VERSION 5.8 ;
BUSBITCHARS "[]" ;
DIVIDERCHAR "/" ;
UNITS
    DATABASE MICRONS 2000 ;
END UNITS

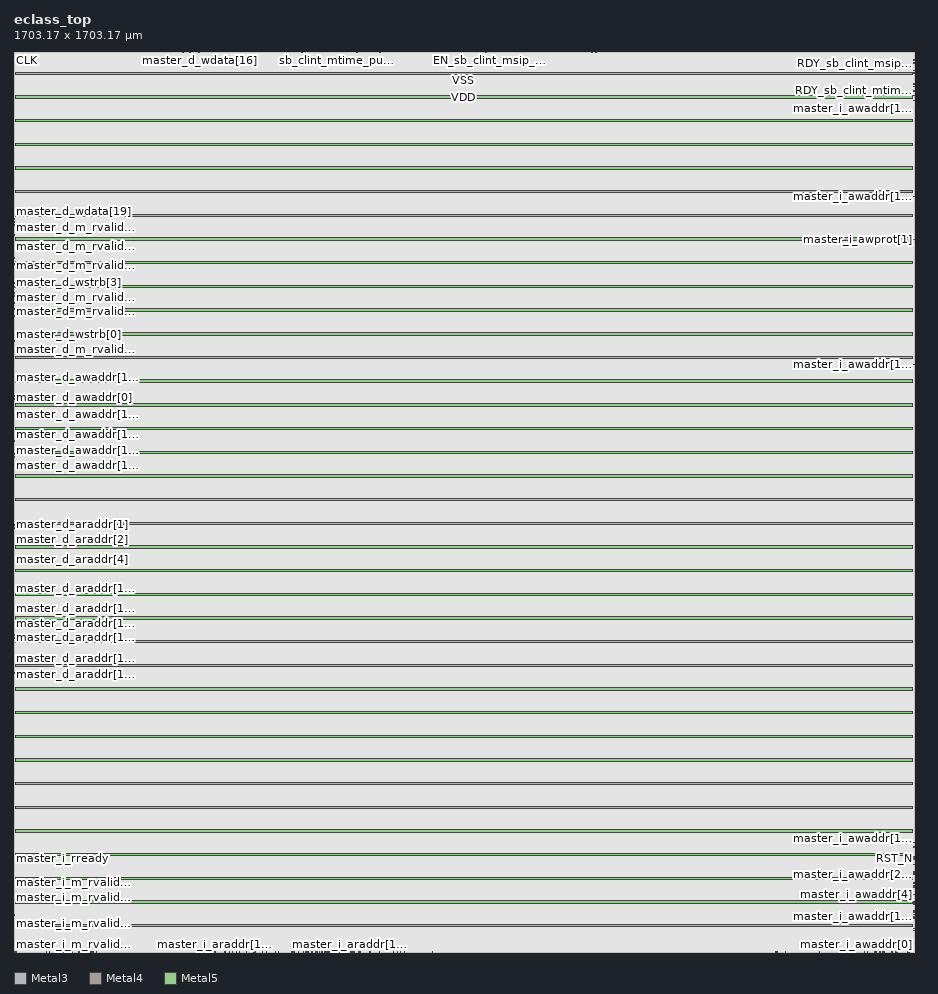
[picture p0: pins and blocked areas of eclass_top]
MACRO eclass_top
  FOREIGN eclass_top 0 0 ;
  CLASS BLOCK ;
  SIZE 1703.175 BY 1703.175 ;
  PIN CLK
    DIRECTION INPUT ;
    USE SIGNAL ;
    PORT
      LAYER Metal3 ;
        RECT  0 1688.26 0.52 1688.54 ;
    END
  END CLK
  PIN EN_sb_clint_msip_put
    DIRECTION INPUT ;
    USE SIGNAL ;
    PORT
      LAYER Metal4 ;
        RECT  900.9 1702.655 901.18 1703.175 ;
    END
  END EN_sb_clint_msip_put
  PIN EN_sb_clint_mtime_put
    DIRECTION INPUT ;
    USE SIGNAL ;
    PORT
      LAYER Metal3 ;
        RECT  0 1243.62 0.52 1243.9 ;
    END
  END EN_sb_clint_mtime_put
  PIN EN_sb_clint_mtip_put
    DIRECTION INPUT ;
    USE SIGNAL ;
    PORT
      LAYER Metal4 ;
        RECT  893.06 1702.655 893.34 1703.175 ;
    END
  END EN_sb_clint_mtip_put
  PIN EN_sb_ext_interrupt_put
    DIRECTION INPUT ;
    USE SIGNAL ;
    PORT
      LAYER Metal4 ;
        RECT  866.18 1702.655 866.46 1703.175 ;
    END
  END EN_sb_ext_interrupt_put
  PIN RDY_sb_clint_msip_put
    DIRECTION OUTPUT ;
    USE SIGNAL ;
    PORT
      LAYER Metal3 ;
        RECT  1702.655 1681.54 1703.175 1681.82 ;
    END
  END RDY_sb_clint_msip_put
  PIN RDY_sb_clint_mtime_put
    DIRECTION OUTPUT ;
    USE SIGNAL ;
    PORT
      LAYER Metal3 ;
        RECT  1702.655 1630.02 1703.175 1630.3 ;
    END
  END RDY_sb_clint_mtime_put
  PIN RDY_sb_clint_mtip_put
    DIRECTION OUTPUT ;
    USE SIGNAL ;
    PORT
      LAYER Metal3 ;
        RECT  1702.655 1662.5 1703.175 1662.78 ;
    END
  END RDY_sb_clint_mtip_put
  PIN RDY_sb_ext_interrupt_put
    DIRECTION OUTPUT ;
    USE SIGNAL ;
    PORT
      LAYER Metal4 ;
        RECT  1643.46 1702.655 1643.74 1703.175 ;
    END
  END RDY_sb_ext_interrupt_put
  PIN RST_N
    DIRECTION INPUT ;
    USE SIGNAL ;
    PORT
      LAYER Metal3 ;
        RECT  1702.655 176.26 1703.175 176.54 ;
    END
  END RST_N
  PIN master_d_araddr[0]
    DIRECTION OUTPUT ;
    USE SIGNAL ;
    PORT
      LAYER Metal3 ;
        RECT  0 782.18 0.52 782.46 ;
    END
  END master_d_araddr[0]
  PIN master_d_araddr[10]
    DIRECTION OUTPUT ;
    USE SIGNAL ;
    PORT
      LAYER Metal3 ;
        RECT  0 686.98 0.52 687.26 ;
    END
  END master_d_araddr[10]
  PIN master_d_araddr[11]
    DIRECTION OUTPUT ;
    USE SIGNAL ;
    PORT
      LAYER Metal3 ;
        RECT  0 689.22 0.52 689.5 ;
    END
  END master_d_araddr[11]
  PIN master_d_araddr[12]
    DIRECTION OUTPUT ;
    USE SIGNAL ;
    PORT
      LAYER Metal3 ;
        RECT  0 665.7 0.52 665.98 ;
    END
  END master_d_araddr[12]
  PIN master_d_araddr[13]
    DIRECTION OUTPUT ;
    USE SIGNAL ;
    PORT
      LAYER Metal3 ;
        RECT  0 660.1 0.52 660.38 ;
    END
  END master_d_araddr[13]
  PIN master_d_araddr[14]
    DIRECTION OUTPUT ;
    USE SIGNAL ;
    PORT
      LAYER Metal3 ;
        RECT  0 636.58 0.52 636.86 ;
    END
  END master_d_araddr[14]
  PIN master_d_araddr[15]
    DIRECTION OUTPUT ;
    USE SIGNAL ;
    PORT
      LAYER Metal3 ;
        RECT  0 524.58 0.52 524.86 ;
    END
  END master_d_araddr[15]
  PIN master_d_araddr[16]
    DIRECTION OUTPUT ;
    USE SIGNAL ;
    PORT
      LAYER Metal3 ;
        RECT  0 527.94 0.52 528.22 ;
    END
  END master_d_araddr[16]
  PIN master_d_araddr[17]
    DIRECTION OUTPUT ;
    USE SIGNAL ;
    PORT
      LAYER Metal3 ;
        RECT  0 523.46 0.52 523.74 ;
    END
  END master_d_araddr[17]
  PIN master_d_araddr[18]
    DIRECTION OUTPUT ;
    USE SIGNAL ;
    PORT
      LAYER Metal3 ;
        RECT  0 609.7 0.52 609.98 ;
    END
  END master_d_araddr[18]
  PIN master_d_araddr[19]
    DIRECTION OUTPUT ;
    USE SIGNAL ;
    PORT
      LAYER Metal3 ;
        RECT  0 570.5 0.52 570.78 ;
    END
  END master_d_araddr[19]
  PIN master_d_araddr[1]
    DIRECTION OUTPUT ;
    USE SIGNAL ;
    PORT
      LAYER Metal3 ;
        RECT  0 807.94 0.52 808.22 ;
    END
  END master_d_araddr[1]
  PIN master_d_araddr[20]
    DIRECTION OUTPUT ;
    USE SIGNAL ;
    PORT
      LAYER Metal3 ;
        RECT  0 546.98 0.52 547.26 ;
    END
  END master_d_araddr[20]
  PIN master_d_araddr[21]
    DIRECTION OUTPUT ;
    USE SIGNAL ;
    PORT
      LAYER Metal3 ;
        RECT  0 620.9 0.52 621.18 ;
    END
  END master_d_araddr[21]
  PIN master_d_araddr[22]
    DIRECTION OUTPUT ;
    USE SIGNAL ;
    PORT
      LAYER Metal3 ;
        RECT  0 594.02 0.52 594.3 ;
    END
  END master_d_araddr[22]
  PIN master_d_araddr[23]
    DIRECTION OUTPUT ;
    USE SIGNAL ;
    PORT
      LAYER Metal3 ;
        RECT  0 608.58 0.52 608.86 ;
    END
  END master_d_araddr[23]
  PIN master_d_araddr[24]
    DIRECTION OUTPUT ;
    USE SIGNAL ;
    PORT
      LAYER Metal3 ;
        RECT  0 633.22 0.52 633.5 ;
    END
  END master_d_araddr[24]
  PIN master_d_araddr[25]
    DIRECTION OUTPUT ;
    USE SIGNAL ;
    PORT
      LAYER Metal3 ;
        RECT  0 622.02 0.52 622.3 ;
    END
  END master_d_araddr[25]
  PIN master_d_araddr[26]
    DIRECTION OUTPUT ;
    USE SIGNAL ;
    PORT
      LAYER Metal3 ;
        RECT  0 599.62 0.52 599.9 ;
    END
  END master_d_araddr[26]
  PIN master_d_araddr[27]
    DIRECTION OUTPUT ;
    USE SIGNAL ;
    PORT
      LAYER Metal3 ;
        RECT  0 567.14 0.52 567.42 ;
    END
  END master_d_araddr[27]
  PIN master_d_araddr[28]
    DIRECTION OUTPUT ;
    USE SIGNAL ;
    PORT
      LAYER Metal3 ;
        RECT  0 568.26 0.52 568.54 ;
    END
  END master_d_araddr[28]
  PIN master_d_araddr[29]
    DIRECTION OUTPUT ;
    USE SIGNAL ;
    PORT
      LAYER Metal3 ;
        RECT  0 670.18 0.52 670.46 ;
    END
  END master_d_araddr[29]
  PIN master_d_araddr[2]
    DIRECTION OUTPUT ;
    USE SIGNAL ;
    PORT
      LAYER Metal3 ;
        RECT  0 781.06 0.52 781.34 ;
    END
  END master_d_araddr[2]
  PIN master_d_araddr[30]
    DIRECTION OUTPUT ;
    USE SIGNAL ;
    PORT
      LAYER Metal3 ;
        RECT  0 669.06 0.52 669.34 ;
    END
  END master_d_araddr[30]
  PIN master_d_araddr[31]
    DIRECTION OUTPUT ;
    USE SIGNAL ;
    PORT
      LAYER Metal3 ;
        RECT  0 645.54 0.52 645.82 ;
    END
  END master_d_araddr[31]
  PIN master_d_araddr[3]
    DIRECTION OUTPUT ;
    USE SIGNAL ;
    PORT
      LAYER Metal3 ;
        RECT  0 757.54 0.52 757.82 ;
    END
  END master_d_araddr[3]
  PIN master_d_araddr[4]
    DIRECTION OUTPUT ;
    USE SIGNAL ;
    PORT
      LAYER Metal3 ;
        RECT  0 741.86 0.52 742.14 ;
    END
  END master_d_araddr[4]
  PIN master_d_araddr[5]
    DIRECTION OUTPUT ;
    USE SIGNAL ;
    PORT
      LAYER Metal3 ;
        RECT  0 738.5 0.52 738.78 ;
    END
  END master_d_araddr[5]
  PIN master_d_araddr[6]
    DIRECTION OUTPUT ;
    USE SIGNAL ;
    PORT
      LAYER Metal3 ;
        RECT  0 711.62 0.52 711.9 ;
    END
  END master_d_araddr[6]
  PIN master_d_araddr[7]
    DIRECTION OUTPUT ;
    USE SIGNAL ;
    PORT
      LAYER Metal3 ;
        RECT  0 740.74 0.52 741.02 ;
    END
  END master_d_araddr[7]
  PIN master_d_araddr[8]
    DIRECTION OUTPUT ;
    USE SIGNAL ;
    PORT
      LAYER Metal3 ;
        RECT  0 712.74 0.52 713.02 ;
    END
  END master_d_araddr[8]
  PIN master_d_araddr[9]
    DIRECTION OUTPUT ;
    USE SIGNAL ;
    PORT
      LAYER Metal3 ;
        RECT  0 721.7 0.52 721.98 ;
    END
  END master_d_araddr[9]
  PIN master_d_arprot[0]
    DIRECTION OUTPUT ;
    USE SIGNAL ;
    PORT
      LAYER Metal3 ;
        RECT  0 663.46 0.52 663.74 ;
    END
  END master_d_arprot[0]
  PIN master_d_arprot[1]
    DIRECTION OUTPUT ;
    USE SIGNAL ;
    PORT
      LAYER Metal3 ;
        RECT  0 564.9 0.52 565.18 ;
    END
  END master_d_arprot[1]
  PIN master_d_arprot[2]
    DIRECTION OUTPUT ;
    USE SIGNAL ;
    PORT
      LAYER Metal3 ;
        RECT  0 566.02 0.52 566.3 ;
    END
  END master_d_arprot[2]
  PIN master_d_arsize[0]
    DIRECTION OUTPUT ;
    USE SIGNAL ;
    PORT
      LAYER Metal3 ;
        RECT  0 804.58 0.52 804.86 ;
    END
  END master_d_arsize[0]
  PIN master_d_arsize[1]
    DIRECTION OUTPUT ;
    USE SIGNAL ;
    PORT
      LAYER Metal3 ;
        RECT  0 802.34 0.52 802.62 ;
    END
  END master_d_arsize[1]
  PIN master_d_arvalid
    DIRECTION OUTPUT ;
    USE SIGNAL ;
    PORT
      LAYER Metal3 ;
        RECT  0 755.3 0.52 755.58 ;
    END
  END master_d_arvalid
  PIN master_d_awaddr[0]
    DIRECTION OUTPUT ;
    USE SIGNAL ;
    PORT
      LAYER Metal3 ;
        RECT  0 1048.74 0.52 1049.02 ;
    END
  END master_d_awaddr[0]
  PIN master_d_awaddr[10]
    DIRECTION OUTPUT ;
    USE SIGNAL ;
    PORT
      LAYER Metal3 ;
        RECT  0 1072.26 0.52 1072.54 ;
    END
  END master_d_awaddr[10]
  PIN master_d_awaddr[11]
    DIRECTION OUTPUT ;
    USE SIGNAL ;
    PORT
      LAYER Metal3 ;
        RECT  0 1065.54 0.52 1065.82 ;
    END
  END master_d_awaddr[11]
  PIN master_d_awaddr[12]
    DIRECTION OUTPUT ;
    USE SIGNAL ;
    PORT
      LAYER Metal3 ;
        RECT  0 1010.66 0.52 1010.94 ;
    END
  END master_d_awaddr[12]
  PIN master_d_awaddr[13]
    DIRECTION OUTPUT ;
    USE SIGNAL ;
    PORT
      LAYER Metal3 ;
        RECT  0 1017.38 0.52 1017.66 ;
    END
  END master_d_awaddr[13]
  PIN master_d_awaddr[14]
    DIRECTION OUTPUT ;
    USE SIGNAL ;
    PORT
      LAYER Metal3 ;
        RECT  0 994.98 0.52 995.26 ;
    END
  END master_d_awaddr[14]
  PIN master_d_awaddr[15]
    DIRECTION OUTPUT ;
    USE SIGNAL ;
    PORT
      LAYER Metal3 ;
        RECT  0 987.14 0.52 987.42 ;
    END
  END master_d_awaddr[15]
  PIN master_d_awaddr[16]
    DIRECTION OUTPUT ;
    USE SIGNAL ;
    PORT
      LAYER Metal3 ;
        RECT  0 963.62 0.52 963.9 ;
    END
  END master_d_awaddr[16]
  PIN master_d_awaddr[17]
    DIRECTION OUTPUT ;
    USE SIGNAL ;
    PORT
      LAYER Metal3 ;
        RECT  0 935.62 0.52 935.9 ;
    END
  END master_d_awaddr[17]
  PIN master_d_awaddr[18]
    DIRECTION OUTPUT ;
    USE SIGNAL ;
    PORT
      LAYER Metal3 ;
        RECT  0 937.86 0.52 938.14 ;
    END
  END master_d_awaddr[18]
  PIN master_d_awaddr[19]
    DIRECTION OUTPUT ;
    USE SIGNAL ;
    PORT
      LAYER Metal3 ;
        RECT  0 959.14 0.52 959.42 ;
    END
  END master_d_awaddr[19]
  PIN master_d_awaddr[1]
    DIRECTION OUTPUT ;
    USE SIGNAL ;
    PORT
      LAYER Metal3 ;
        RECT  0 1000.58 0.52 1000.86 ;
    END
  END master_d_awaddr[1]
  PIN master_d_awaddr[20]
    DIRECTION OUTPUT ;
    USE SIGNAL ;
    PORT
      LAYER Metal3 ;
        RECT  0 962.5 0.52 962.78 ;
    END
  END master_d_awaddr[20]
  PIN master_d_awaddr[21]
    DIRECTION OUTPUT ;
    USE SIGNAL ;
    PORT
      LAYER Metal3 ;
        RECT  0 944.58 0.52 944.86 ;
    END
  END master_d_awaddr[21]
  PIN master_d_awaddr[22]
    DIRECTION OUTPUT ;
    USE SIGNAL ;
    PORT
      LAYER Metal3 ;
        RECT  0 965.86 0.52 966.14 ;
    END
  END master_d_awaddr[22]
  PIN master_d_awaddr[23]
    DIRECTION OUTPUT ;
    USE SIGNAL ;
    PORT
      LAYER Metal3 ;
        RECT  0 943.46 0.52 943.74 ;
    END
  END master_d_awaddr[23]
  PIN master_d_awaddr[24]
    DIRECTION OUTPUT ;
    USE SIGNAL ;
    PORT
      LAYER Metal3 ;
        RECT  0 966.98 0.52 967.26 ;
    END
  END master_d_awaddr[24]
  PIN master_d_awaddr[25]
    DIRECTION OUTPUT ;
    USE SIGNAL ;
    PORT
      LAYER Metal3 ;
        RECT  0 942.34 0.52 942.62 ;
    END
  END master_d_awaddr[25]
  PIN master_d_awaddr[26]
    DIRECTION OUTPUT ;
    USE SIGNAL ;
    PORT
      LAYER Metal3 ;
        RECT  0 941.22 0.52 941.5 ;
    END
  END master_d_awaddr[26]
  PIN master_d_awaddr[27]
    DIRECTION OUTPUT ;
    USE SIGNAL ;
    PORT
      LAYER Metal3 ;
        RECT  0 938.98 0.52 939.26 ;
    END
  END master_d_awaddr[27]
  PIN master_d_awaddr[28]
    DIRECTION OUTPUT ;
    USE SIGNAL ;
    PORT
      LAYER Metal3 ;
        RECT  0 936.74 0.52 937.02 ;
    END
  END master_d_awaddr[28]
  PIN master_d_awaddr[29]
    DIRECTION OUTPUT ;
    USE SIGNAL ;
    PORT
      LAYER Metal3 ;
        RECT  0 969.22 0.52 969.5 ;
    END
  END master_d_awaddr[29]
  PIN master_d_awaddr[2]
    DIRECTION OUTPUT ;
    USE SIGNAL ;
    PORT
      LAYER Metal3 ;
        RECT  0 989.38 0.52 989.66 ;
    END
  END master_d_awaddr[2]
  PIN master_d_awaddr[30]
    DIRECTION OUTPUT ;
    USE SIGNAL ;
    PORT
      LAYER Metal3 ;
        RECT  0 977.06 0.52 977.34 ;
    END
  END master_d_awaddr[30]
  PIN master_d_awaddr[31]
    DIRECTION OUTPUT ;
    USE SIGNAL ;
    PORT
      LAYER Metal3 ;
        RECT  0 1025.22 0.52 1025.5 ;
    END
  END master_d_awaddr[31]
  PIN master_d_awaddr[3]
    DIRECTION OUTPUT ;
    USE SIGNAL ;
    PORT
      LAYER Metal3 ;
        RECT  0 986.02 0.52 986.3 ;
    END
  END master_d_awaddr[3]
  PIN master_d_awaddr[4]
    DIRECTION OUTPUT ;
    USE SIGNAL ;
    PORT
      LAYER Metal3 ;
        RECT  0 1058.82 0.52 1059.1 ;
    END
  END master_d_awaddr[4]
  PIN master_d_awaddr[5]
    DIRECTION OUTPUT ;
    USE SIGNAL ;
    PORT
      LAYER Metal3 ;
        RECT  0 1005.06 0.52 1005.34 ;
    END
  END master_d_awaddr[5]
  PIN master_d_awaddr[6]
    DIRECTION OUTPUT ;
    USE SIGNAL ;
    PORT
      LAYER Metal3 ;
        RECT  0 1066.66 0.52 1066.94 ;
    END
  END master_d_awaddr[6]
  PIN master_d_awaddr[7]
    DIRECTION OUTPUT ;
    USE SIGNAL ;
    PORT
      LAYER Metal3 ;
        RECT  0 1068.9 0.52 1069.18 ;
    END
  END master_d_awaddr[7]
  PIN master_d_awaddr[8]
    DIRECTION OUTPUT ;
    USE SIGNAL ;
    PORT
      LAYER Metal3 ;
        RECT  0 1007.3 0.52 1007.58 ;
    END
  END master_d_awaddr[8]
  PIN master_d_awaddr[9]
    DIRECTION OUTPUT ;
    USE SIGNAL ;
    PORT
      LAYER Metal3 ;
        RECT  0 1071.14 0.52 1071.42 ;
    END
  END master_d_awaddr[9]
  PIN master_d_awprot[0]
    DIRECTION OUTPUT ;
    USE SIGNAL ;
    PORT
      LAYER Metal3 ;
        RECT  0 940.1 0.52 940.38 ;
    END
  END master_d_awprot[0]
  PIN master_d_awprot[1]
    DIRECTION OUTPUT ;
    USE SIGNAL ;
    PORT
      LAYER Metal3 ;
        RECT  0 945.7 0.52 945.98 ;
    END
  END master_d_awprot[1]
  PIN master_d_awprot[2]
    DIRECTION OUTPUT ;
    USE SIGNAL ;
    PORT
      LAYER Metal3 ;
        RECT  0 946.82 0.52 947.1 ;
    END
  END master_d_awprot[2]
  PIN master_d_awsize[0]
    DIRECTION OUTPUT ;
    USE SIGNAL ;
    PORT
      LAYER Metal3 ;
        RECT  0 993.86 0.52 994.14 ;
    END
  END master_d_awsize[0]
  PIN master_d_awsize[1]
    DIRECTION OUTPUT ;
    USE SIGNAL ;
    PORT
      LAYER Metal3 ;
        RECT  0 996.1 0.52 996.38 ;
    END
  END master_d_awsize[1]
  PIN master_d_awvalid
    DIRECTION OUTPUT ;
    USE SIGNAL ;
    PORT
      LAYER Metal3 ;
        RECT  0 1046.5 0.52 1046.78 ;
    END
  END master_d_awvalid
  PIN master_d_bready
    DIRECTION OUTPUT ;
    USE SIGNAL ;
    PORT
      LAYER Metal3 ;
        RECT  0 1052.1 0.52 1052.38 ;
    END
  END master_d_bready
  PIN master_d_m_arready_arready
    DIRECTION INPUT ;
    USE SIGNAL ;
    PORT
      LAYER Metal3 ;
        RECT  0 739.62 0.52 739.9 ;
    END
  END master_d_m_arready_arready
  PIN master_d_m_awready_awready
    DIRECTION INPUT ;
    USE SIGNAL ;
    PORT
      LAYER Metal3 ;
        RECT  0 1049.86 0.52 1050.14 ;
    END
  END master_d_m_awready_awready
  PIN master_d_m_bvalid_bresp[0]
    DIRECTION INPUT ;
    USE SIGNAL ;
    PORT
      LAYER Metal3 ;
        RECT  0 1064.42 0.52 1064.7 ;
    END
  END master_d_m_bvalid_bresp[0]
  PIN master_d_m_bvalid_bresp[1]
    DIRECTION INPUT ;
    USE SIGNAL ;
    PORT
      LAYER Metal3 ;
        RECT  0 1074.5 0.52 1074.78 ;
    END
  END master_d_m_bvalid_bresp[1]
  PIN master_d_m_bvalid_bvalid
    DIRECTION INPUT ;
    USE SIGNAL ;
    PORT
      LAYER Metal3 ;
        RECT  0 1047.62 0.52 1047.9 ;
    END
  END master_d_m_bvalid_bvalid
  PIN master_d_m_rvalid_rdata[0]
    DIRECTION INPUT ;
    USE SIGNAL ;
    PORT
      LAYER Metal3 ;
        RECT  0 1212.26 0.52 1212.54 ;
    END
  END master_d_m_rvalid_rdata[0]
  PIN master_d_m_rvalid_rdata[10]
    DIRECTION INPUT ;
    USE SIGNAL ;
    PORT
      LAYER Metal3 ;
        RECT  0 1239.14 0.52 1239.42 ;
    END
  END master_d_m_rvalid_rdata[10]
  PIN master_d_m_rvalid_rdata[11]
    DIRECTION INPUT ;
    USE SIGNAL ;
    PORT
      LAYER Metal3 ;
        RECT  0 1217.86 0.52 1218.14 ;
    END
  END master_d_m_rvalid_rdata[11]
  PIN master_d_m_rvalid_rdata[12]
    DIRECTION INPUT ;
    USE SIGNAL ;
    PORT
      LAYER Metal3 ;
        RECT  0 1218.98 0.52 1219.26 ;
    END
  END master_d_m_rvalid_rdata[12]
  PIN master_d_m_rvalid_rdata[13]
    DIRECTION INPUT ;
    USE SIGNAL ;
    PORT
      LAYER Metal3 ;
        RECT  0 1335.46 0.52 1335.74 ;
    END
  END master_d_m_rvalid_rdata[13]
  PIN master_d_m_rvalid_rdata[14]
    DIRECTION INPUT ;
    USE SIGNAL ;
    PORT
      LAYER Metal3 ;
        RECT  0 1314.18 0.52 1314.46 ;
    END
  END master_d_m_rvalid_rdata[14]
  PIN master_d_m_rvalid_rdata[15]
    DIRECTION INPUT ;
    USE SIGNAL ;
    PORT
      LAYER Metal3 ;
        RECT  0 1264.9 0.52 1265.18 ;
    END
  END master_d_m_rvalid_rdata[15]
  PIN master_d_m_rvalid_rdata[16]
    DIRECTION INPUT ;
    USE SIGNAL ;
    PORT
      LAYER Metal3 ;
        RECT  0 1262.66 0.52 1262.94 ;
    END
  END master_d_m_rvalid_rdata[16]
  PIN master_d_m_rvalid_rdata[17]
    DIRECTION INPUT ;
    USE SIGNAL ;
    PORT
      LAYER Metal3 ;
        RECT  0 1290.66 0.52 1290.94 ;
    END
  END master_d_m_rvalid_rdata[17]
  PIN master_d_m_rvalid_rdata[18]
    DIRECTION INPUT ;
    USE SIGNAL ;
    PORT
      LAYER Metal3 ;
        RECT  0 1289.54 0.52 1289.82 ;
    END
  END master_d_m_rvalid_rdata[18]
  PIN master_d_m_rvalid_rdata[19]
    DIRECTION INPUT ;
    USE SIGNAL ;
    PORT
      LAYER Metal3 ;
        RECT  0 1313.06 0.52 1313.34 ;
    END
  END master_d_m_rvalid_rdata[19]
  PIN master_d_m_rvalid_rdata[1]
    DIRECTION INPUT ;
    USE SIGNAL ;
    PORT
      LAYER Metal3 ;
        RECT  0 1164.1 0.52 1164.38 ;
    END
  END master_d_m_rvalid_rdata[1]
  PIN master_d_m_rvalid_rdata[20]
    DIRECTION INPUT ;
    USE SIGNAL ;
    PORT
      LAYER Metal3 ;
        RECT  0 1356.74 0.52 1357.02 ;
    END
  END master_d_m_rvalid_rdata[20]
  PIN master_d_m_rvalid_rdata[21]
    DIRECTION INPUT ;
    USE SIGNAL ;
    PORT
      LAYER Metal3 ;
        RECT  0 1336.58 0.52 1336.86 ;
    END
  END master_d_m_rvalid_rdata[21]
  PIN master_d_m_rvalid_rdata[22]
    DIRECTION INPUT ;
    USE SIGNAL ;
    PORT
      LAYER Metal3 ;
        RECT  0 1355.62 0.52 1355.9 ;
    END
  END master_d_m_rvalid_rdata[22]
  PIN master_d_m_rvalid_rdata[23]
    DIRECTION INPUT ;
    USE SIGNAL ;
    PORT
      LAYER Metal3 ;
        RECT  0 1354.5 0.52 1354.78 ;
    END
  END master_d_m_rvalid_rdata[23]
  PIN master_d_m_rvalid_rdata[24]
    DIRECTION INPUT ;
    USE SIGNAL ;
    PORT
      LAYER Metal3 ;
        RECT  0 1353.38 0.52 1353.66 ;
    END
  END master_d_m_rvalid_rdata[24]
  PIN master_d_m_rvalid_rdata[25]
    DIRECTION INPUT ;
    USE SIGNAL ;
    PORT
      LAYER Metal3 ;
        RECT  0 1357.86 0.52 1358.14 ;
    END
  END master_d_m_rvalid_rdata[25]
  PIN master_d_m_rvalid_rdata[26]
    DIRECTION INPUT ;
    USE SIGNAL ;
    PORT
      LAYER Metal3 ;
        RECT  0 1380.26 0.52 1380.54 ;
    END
  END master_d_m_rvalid_rdata[26]
  PIN master_d_m_rvalid_rdata[27]
    DIRECTION INPUT ;
    USE SIGNAL ;
    PORT
      LAYER Metal3 ;
        RECT  0 1376.9 0.52 1377.18 ;
    END
  END master_d_m_rvalid_rdata[27]
  PIN master_d_m_rvalid_rdata[28]
    DIRECTION INPUT ;
    USE SIGNAL ;
    PORT
      LAYER Metal3 ;
        RECT  0 1381.38 0.52 1381.66 ;
    END
  END master_d_m_rvalid_rdata[28]
  PIN master_d_m_rvalid_rdata[29]
    DIRECTION INPUT ;
    USE SIGNAL ;
    PORT
      LAYER Metal3 ;
        RECT  0 1311.94 0.52 1312.22 ;
    END
  END master_d_m_rvalid_rdata[29]
  PIN master_d_m_rvalid_rdata[2]
    DIRECTION INPUT ;
    USE SIGNAL ;
    PORT
      LAYER Metal3 ;
        RECT  0 1187.62 0.52 1187.9 ;
    END
  END master_d_m_rvalid_rdata[2]
  PIN master_d_m_rvalid_rdata[30]
    DIRECTION INPUT ;
    USE SIGNAL ;
    PORT
      LAYER Metal3 ;
        RECT  0 1375.78 0.52 1376.06 ;
    END
  END master_d_m_rvalid_rdata[30]
  PIN master_d_m_rvalid_rdata[31]
    DIRECTION INPUT ;
    USE SIGNAL ;
    PORT
      LAYER Metal3 ;
        RECT  0 1338.82 0.52 1339.1 ;
    END
  END master_d_m_rvalid_rdata[31]
  PIN master_d_m_rvalid_rdata[3]
    DIRECTION INPUT ;
    USE SIGNAL ;
    PORT
      LAYER Metal3 ;
        RECT  0 1249.22 0.52 1249.5 ;
    END
  END master_d_m_rvalid_rdata[3]
  PIN master_d_m_rvalid_rdata[4]
    DIRECTION INPUT ;
    USE SIGNAL ;
    PORT
      LAYER Metal3 ;
        RECT  0 1244.74 0.52 1245.02 ;
    END
  END master_d_m_rvalid_rdata[4]
  PIN master_d_m_rvalid_rdata[5]
    DIRECTION INPUT ;
    USE SIGNAL ;
    PORT
      LAYER Metal3 ;
        RECT  0 1246.98 0.52 1247.26 ;
    END
  END master_d_m_rvalid_rdata[5]
  PIN master_d_m_rvalid_rdata[6]
    DIRECTION INPUT ;
    USE SIGNAL ;
    PORT
      LAYER Metal3 ;
        RECT  0 1240.26 0.52 1240.54 ;
    END
  END master_d_m_rvalid_rdata[6]
  PIN master_d_m_rvalid_rdata[7]
    DIRECTION INPUT ;
    USE SIGNAL ;
    PORT
      LAYER Metal3 ;
        RECT  0 1227.94 0.52 1228.22 ;
    END
  END master_d_m_rvalid_rdata[7]
  PIN master_d_m_rvalid_rdata[8]
    DIRECTION INPUT ;
    USE SIGNAL ;
    PORT
      LAYER Metal3 ;
        RECT  0 1213.38 0.52 1213.66 ;
    END
  END master_d_m_rvalid_rdata[8]
  PIN master_d_m_rvalid_rdata[9]
    DIRECTION INPUT ;
    USE SIGNAL ;
    PORT
      LAYER Metal3 ;
        RECT  0 1214.5 0.52 1214.78 ;
    END
  END master_d_m_rvalid_rdata[9]
  PIN master_d_m_rvalid_rresp[0]
    DIRECTION INPUT ;
    USE SIGNAL ;
    PORT
      LAYER Metal3 ;
        RECT  0 1263.78 0.52 1264.06 ;
    END
  END master_d_m_rvalid_rresp[0]
  PIN master_d_m_rvalid_rresp[1]
    DIRECTION INPUT ;
    USE SIGNAL ;
    PORT
      LAYER Metal3 ;
        RECT  0 1140.58 0.52 1140.86 ;
    END
  END master_d_m_rvalid_rresp[1]
  PIN master_d_m_rvalid_rvalid
    DIRECTION INPUT ;
    USE SIGNAL ;
    PORT
      LAYER Metal3 ;
        RECT  0 1111.46 0.52 1111.74 ;
    END
  END master_d_m_rvalid_rvalid
  PIN master_d_m_wready_wready
    DIRECTION INPUT ;
    USE SIGNAL ;
    PORT
      LAYER Metal3 ;
        RECT  0 1110.34 0.52 1110.62 ;
    END
  END master_d_m_wready_wready
  PIN master_d_rready
    DIRECTION OUTPUT ;
    USE SIGNAL ;
    PORT
      LAYER Metal3 ;
        RECT  0 1123.78 0.52 1124.06 ;
    END
  END master_d_rready
  PIN master_d_wdata[0]
    DIRECTION OUTPUT ;
    USE SIGNAL ;
    PORT
      LAYER Metal4 ;
        RECT  300.58 1702.655 300.86 1703.175 ;
    END
  END master_d_wdata[0]
  PIN master_d_wdata[10]
    DIRECTION OUTPUT ;
    USE SIGNAL ;
    PORT
      LAYER Metal4 ;
        RECT  345.38 1702.655 345.66 1703.175 ;
    END
  END master_d_wdata[10]
  PIN master_d_wdata[11]
    DIRECTION OUTPUT ;
    USE SIGNAL ;
    PORT
      LAYER Metal4 ;
        RECT  370.02 1702.655 370.3 1703.175 ;
    END
  END master_d_wdata[11]
  PIN master_d_wdata[12]
    DIRECTION OUTPUT ;
    USE SIGNAL ;
    PORT
      LAYER Metal4 ;
        RECT  395.78 1702.655 396.06 1703.175 ;
    END
  END master_d_wdata[12]
  PIN master_d_wdata[13]
    DIRECTION OUTPUT ;
    USE SIGNAL ;
    PORT
      LAYER Metal3 ;
        RECT  0 1388.1 0.52 1388.38 ;
    END
  END master_d_wdata[13]
  PIN master_d_wdata[14]
    DIRECTION OUTPUT ;
    USE SIGNAL ;
    PORT
      LAYER Metal4 ;
        RECT  398.02 1702.655 398.3 1703.175 ;
    END
  END master_d_wdata[14]
  PIN master_d_wdata[15]
    DIRECTION OUTPUT ;
    USE SIGNAL ;
    PORT
      LAYER Metal4 ;
        RECT  383.46 1702.655 383.74 1703.175 ;
    END
  END master_d_wdata[15]
  PIN master_d_wdata[16]
    DIRECTION OUTPUT ;
    USE SIGNAL ;
    PORT
      LAYER Metal4 ;
        RECT  352.1 1702.655 352.38 1703.175 ;
    END
  END master_d_wdata[16]
  PIN master_d_wdata[17]
    DIRECTION OUTPUT ;
    USE SIGNAL ;
    PORT
      LAYER Metal4 ;
        RECT  350.98 1702.655 351.26 1703.175 ;
    END
  END master_d_wdata[17]
  PIN master_d_wdata[18]
    DIRECTION OUTPUT ;
    USE SIGNAL ;
    PORT
      LAYER Metal4 ;
        RECT  302.82 1702.655 303.1 1703.175 ;
    END
  END master_d_wdata[18]
  PIN master_d_wdata[19]
    DIRECTION OUTPUT ;
    USE SIGNAL ;
    PORT
      LAYER Metal3 ;
        RECT  0 1386.98 0.52 1387.26 ;
    END
  END master_d_wdata[19]
  PIN master_d_wdata[1]
    DIRECTION OUTPUT ;
    USE SIGNAL ;
    PORT
      LAYER Metal4 ;
        RECT  333.06 1702.655 333.34 1703.175 ;
    END
  END master_d_wdata[1]
  PIN master_d_wdata[20]
    DIRECTION OUTPUT ;
    USE SIGNAL ;
    PORT
      LAYER Metal4 ;
        RECT  381.22 1702.655 381.5 1703.175 ;
    END
  END master_d_wdata[20]
  PIN master_d_wdata[21]
    DIRECTION OUTPUT ;
    USE SIGNAL ;
    PORT
      LAYER Metal3 ;
        RECT  0 1364.58 0.52 1364.86 ;
    END
  END master_d_wdata[21]
  PIN master_d_wdata[22]
    DIRECTION OUTPUT ;
    USE SIGNAL ;
    PORT
      LAYER Metal4 ;
        RECT  327.46 1702.655 327.74 1703.175 ;
    END
  END master_d_wdata[22]
  PIN master_d_wdata[23]
    DIRECTION OUTPUT ;
    USE SIGNAL ;
    PORT
      LAYER Metal4 ;
        RECT  321.86 1702.655 322.14 1703.175 ;
    END
  END master_d_wdata[23]
  PIN master_d_wdata[24]
    DIRECTION OUTPUT ;
    USE SIGNAL ;
    PORT
      LAYER Metal4 ;
        RECT  328.58 1702.655 328.86 1703.175 ;
    END
  END master_d_wdata[24]
  PIN master_d_wdata[25]
    DIRECTION OUTPUT ;
    USE SIGNAL ;
    PORT
      LAYER Metal4 ;
        RECT  375.62 1702.655 375.9 1703.175 ;
    END
  END master_d_wdata[25]
  PIN master_d_wdata[26]
    DIRECTION OUTPUT ;
    USE SIGNAL ;
    PORT
      LAYER Metal4 ;
        RECT  349.86 1702.655 350.14 1703.175 ;
    END
  END master_d_wdata[26]
  PIN master_d_wdata[27]
    DIRECTION OUTPUT ;
    USE SIGNAL ;
    PORT
      LAYER Metal3 ;
        RECT  0 1301.86 0.52 1302.14 ;
    END
  END master_d_wdata[27]
  PIN master_d_wdata[28]
    DIRECTION OUTPUT ;
    USE SIGNAL ;
    PORT
      LAYER Metal4 ;
        RECT  378.98 1702.655 379.26 1703.175 ;
    END
  END master_d_wdata[28]
  PIN master_d_wdata[29]
    DIRECTION OUTPUT ;
    USE SIGNAL ;
    PORT
      LAYER Metal4 ;
        RECT  376.74 1702.655 377.02 1703.175 ;
    END
  END master_d_wdata[29]
  PIN master_d_wdata[2]
    DIRECTION OUTPUT ;
    USE SIGNAL ;
    PORT
      LAYER Metal3 ;
        RECT  0 1341.06 0.52 1341.34 ;
    END
  END master_d_wdata[2]
  PIN master_d_wdata[30]
    DIRECTION OUTPUT ;
    USE SIGNAL ;
    PORT
      LAYER Metal3 ;
        RECT  0 1339.94 0.52 1340.22 ;
    END
  END master_d_wdata[30]
  PIN master_d_wdata[31]
    DIRECTION OUTPUT ;
    USE SIGNAL ;
    PORT
      LAYER Metal3 ;
        RECT  0 1258.18 0.52 1258.46 ;
    END
  END master_d_wdata[31]
  PIN master_d_wdata[3]
    DIRECTION OUTPUT ;
    USE SIGNAL ;
    PORT
      LAYER Metal3 ;
        RECT  0 1365.7 0.52 1365.98 ;
    END
  END master_d_wdata[3]
  PIN master_d_wdata[4]
    DIRECTION OUTPUT ;
    USE SIGNAL ;
    PORT
      LAYER Metal4 ;
        RECT  331.94 1702.655 332.22 1703.175 ;
    END
  END master_d_wdata[4]
  PIN master_d_wdata[5]
    DIRECTION OUTPUT ;
    USE SIGNAL ;
    PORT
      LAYER Metal4 ;
        RECT  320.74 1702.655 321.02 1703.175 ;
    END
  END master_d_wdata[5]
  PIN master_d_wdata[6]
    DIRECTION OUTPUT ;
    USE SIGNAL ;
    PORT
      LAYER Metal4 ;
        RECT  319.62 1702.655 319.9 1703.175 ;
    END
  END master_d_wdata[6]
  PIN master_d_wdata[7]
    DIRECTION OUTPUT ;
    USE SIGNAL ;
    PORT
      LAYER Metal4 ;
        RECT  342.02 1702.655 342.3 1703.175 ;
    END
  END master_d_wdata[7]
  PIN master_d_wdata[8]
    DIRECTION OUTPUT ;
    USE SIGNAL ;
    PORT
      LAYER Metal4 ;
        RECT  357.7 1702.655 357.98 1703.175 ;
    END
  END master_d_wdata[8]
  PIN master_d_wdata[9]
    DIRECTION OUTPUT ;
    USE SIGNAL ;
    PORT
      LAYER Metal4 ;
        RECT  372.26 1702.655 372.54 1703.175 ;
    END
  END master_d_wdata[9]
  PIN master_d_wstrb[0]
    DIRECTION OUTPUT ;
    USE SIGNAL ;
    PORT
      LAYER Metal3 ;
        RECT  0 1154.02 0.52 1154.3 ;
    END
  END master_d_wstrb[0]
  PIN master_d_wstrb[1]
    DIRECTION OUTPUT ;
    USE SIGNAL ;
    PORT
      LAYER Metal3 ;
        RECT  0 1157.38 0.52 1157.66 ;
    END
  END master_d_wstrb[1]
  PIN master_d_wstrb[2]
    DIRECTION OUTPUT ;
    USE SIGNAL ;
    PORT
      LAYER Metal3 ;
        RECT  0 1133.86 0.52 1134.14 ;
    END
  END master_d_wstrb[2]
  PIN master_d_wstrb[3]
    DIRECTION OUTPUT ;
    USE SIGNAL ;
    PORT
      LAYER Metal3 ;
        RECT  0 1266.02 0.52 1266.3 ;
    END
  END master_d_wstrb[3]
  PIN master_d_wvalid
    DIRECTION OUTPUT ;
    USE SIGNAL ;
    PORT
      LAYER Metal3 ;
        RECT  0 1128.26 0.52 1128.54 ;
    END
  END master_d_wvalid
  PIN master_i_araddr[0]
    DIRECTION OUTPUT ;
    USE SIGNAL ;
    PORT
      LAYER Metal4 ;
        RECT  615.3 0 615.58 0.52 ;
    END
  END master_i_araddr[0]
  PIN master_i_araddr[10]
    DIRECTION OUTPUT ;
    USE SIGNAL ;
    PORT
      LAYER Metal4 ;
        RECT  636.58 0 636.86 0.52 ;
    END
  END master_i_araddr[10]
  PIN master_i_araddr[11]
    DIRECTION OUTPUT ;
    USE SIGNAL ;
    PORT
      LAYER Metal4 ;
        RECT  529.06 0 529.34 0.52 ;
    END
  END master_i_araddr[11]
  PIN master_i_araddr[12]
    DIRECTION OUTPUT ;
    USE SIGNAL ;
    PORT
      LAYER Metal4 ;
        RECT  527.94 0 528.22 0.52 ;
    END
  END master_i_araddr[12]
  PIN master_i_araddr[13]
    DIRECTION OUTPUT ;
    USE SIGNAL ;
    PORT
      LAYER Metal4 ;
        RECT  531.3 0 531.58 0.52 ;
    END
  END master_i_araddr[13]
  PIN master_i_araddr[14]
    DIRECTION OUTPUT ;
    USE SIGNAL ;
    PORT
      LAYER Metal4 ;
        RECT  439.46 0 439.74 0.52 ;
    END
  END master_i_araddr[14]
  PIN master_i_araddr[15]
    DIRECTION OUTPUT ;
    USE SIGNAL ;
    PORT
      LAYER Metal4 ;
        RECT  399.14 0 399.42 0.52 ;
    END
  END master_i_araddr[15]
  PIN master_i_araddr[16]
    DIRECTION OUTPUT ;
    USE SIGNAL ;
    PORT
      LAYER Metal4 ;
        RECT  372.26 0 372.54 0.52 ;
    END
  END master_i_araddr[16]
  PIN master_i_araddr[17]
    DIRECTION OUTPUT ;
    USE SIGNAL ;
    PORT
      LAYER Metal4 ;
        RECT  380.1 0 380.38 0.52 ;
    END
  END master_i_araddr[17]
  PIN master_i_araddr[18]
    DIRECTION OUTPUT ;
    USE SIGNAL ;
    PORT
      LAYER Metal4 ;
        RECT  408.1 0 408.38 0.52 ;
    END
  END master_i_araddr[18]
  PIN master_i_araddr[19]
    DIRECTION OUTPUT ;
    USE SIGNAL ;
    PORT
      LAYER Metal4 ;
        RECT  427.14 0 427.42 0.52 ;
    END
  END master_i_araddr[19]
  PIN master_i_araddr[1]
    DIRECTION OUTPUT ;
    USE SIGNAL ;
    PORT
      LAYER Metal4 ;
        RECT  619.78 0 620.06 0.52 ;
    END
  END master_i_araddr[1]
  PIN master_i_araddr[20]
    DIRECTION OUTPUT ;
    USE SIGNAL ;
    PORT
      LAYER Metal4 ;
        RECT  413.7 0 413.98 0.52 ;
    END
  END master_i_araddr[20]
  PIN master_i_araddr[21]
    DIRECTION OUTPUT ;
    USE SIGNAL ;
    PORT
      LAYER Metal4 ;
        RECT  365.54 0 365.82 0.52 ;
    END
  END master_i_araddr[21]
  PIN master_i_araddr[22]
    DIRECTION OUTPUT ;
    USE SIGNAL ;
    PORT
      LAYER Metal4 ;
        RECT  420.42 0 420.7 0.52 ;
    END
  END master_i_araddr[22]
  PIN master_i_araddr[23]
    DIRECTION OUTPUT ;
    USE SIGNAL ;
    PORT
      LAYER Metal4 ;
        RECT  524.58 0 524.86 0.52 ;
    END
  END master_i_araddr[23]
  PIN master_i_araddr[24]
    DIRECTION OUTPUT ;
    USE SIGNAL ;
    PORT
      LAYER Metal4 ;
        RECT  470.82 0 471.1 0.52 ;
    END
  END master_i_araddr[24]
  PIN master_i_araddr[25]
    DIRECTION OUTPUT ;
    USE SIGNAL ;
    PORT
      LAYER Metal4 ;
        RECT  501.06 0 501.34 0.52 ;
    END
  END master_i_araddr[25]
  PIN master_i_araddr[26]
    DIRECTION OUTPUT ;
    USE SIGNAL ;
    PORT
      LAYER Metal4 ;
        RECT  477.54 0 477.82 0.52 ;
    END
  END master_i_araddr[26]
  PIN master_i_araddr[27]
    DIRECTION OUTPUT ;
    USE SIGNAL ;
    PORT
      LAYER Metal4 ;
        RECT  494.34 0 494.62 0.52 ;
    END
  END master_i_araddr[27]
  PIN master_i_araddr[28]
    DIRECTION OUTPUT ;
    USE SIGNAL ;
    PORT
      LAYER Metal4 ;
        RECT  454.02 0 454.3 0.52 ;
    END
  END master_i_araddr[28]
  PIN master_i_araddr[29]
    DIRECTION OUTPUT ;
    USE SIGNAL ;
    PORT
      LAYER Metal4 ;
        RECT  525.7 0 525.98 0.52 ;
    END
  END master_i_araddr[29]
  PIN master_i_araddr[2]
    DIRECTION OUTPUT ;
    USE SIGNAL ;
    PORT
      LAYER Metal4 ;
        RECT  588.42 0 588.7 0.52 ;
    END
  END master_i_araddr[2]
  PIN master_i_araddr[30]
    DIRECTION OUTPUT ;
    USE SIGNAL ;
    PORT
      LAYER Metal4 ;
        RECT  456.26 0 456.54 0.52 ;
    END
  END master_i_araddr[30]
  PIN master_i_araddr[31]
    DIRECTION OUTPUT ;
    USE SIGNAL ;
    PORT
      LAYER Metal4 ;
        RECT  552.58 0 552.86 0.52 ;
    END
  END master_i_araddr[31]
  PIN master_i_araddr[3]
    DIRECTION OUTPUT ;
    USE SIGNAL ;
    PORT
      LAYER Metal4 ;
        RECT  601.86 0 602.14 0.52 ;
    END
  END master_i_araddr[3]
  PIN master_i_araddr[4]
    DIRECTION OUTPUT ;
    USE SIGNAL ;
    PORT
      LAYER Metal4 ;
        RECT  644.42 0 644.7 0.52 ;
    END
  END master_i_araddr[4]
  PIN master_i_araddr[5]
    DIRECTION OUTPUT ;
    USE SIGNAL ;
    PORT
      LAYER Metal4 ;
        RECT  639.94 0 640.22 0.52 ;
    END
  END master_i_araddr[5]
  PIN master_i_araddr[6]
    DIRECTION OUTPUT ;
    USE SIGNAL ;
    PORT
      LAYER Metal4 ;
        RECT  642.18 0 642.46 0.52 ;
    END
  END master_i_araddr[6]
  PIN master_i_araddr[7]
    DIRECTION OUTPUT ;
    USE SIGNAL ;
    PORT
      LAYER Metal4 ;
        RECT  548.1 0 548.38 0.52 ;
    END
  END master_i_araddr[7]
  PIN master_i_araddr[8]
    DIRECTION OUTPUT ;
    USE SIGNAL ;
    PORT
      LAYER Metal4 ;
        RECT  594.02 0 594.3 0.52 ;
    END
  END master_i_araddr[8]
  PIN master_i_araddr[9]
    DIRECTION OUTPUT ;
    USE SIGNAL ;
    PORT
      LAYER Metal4 ;
        RECT  571.62 0 571.9 0.52 ;
    END
  END master_i_araddr[9]
  PIN master_i_arprot[0]
    DIRECTION OUTPUT ;
    USE SIGNAL ;
    PORT
      LAYER Metal4 ;
        RECT  562.66 0 562.94 0.52 ;
    END
  END master_i_arprot[0]
  PIN master_i_arprot[1]
    DIRECTION OUTPUT ;
    USE SIGNAL ;
    PORT
      LAYER Metal4 ;
        RECT  596.26 0 596.54 0.52 ;
    END
  END master_i_arprot[1]
  PIN master_i_arprot[2]
    DIRECTION OUTPUT ;
    USE SIGNAL ;
    PORT
      LAYER Metal4 ;
        RECT  592.9 0 593.18 0.52 ;
    END
  END master_i_arprot[2]
  PIN master_i_arsize[0]
    DIRECTION OUTPUT ;
    USE SIGNAL ;
    PORT
      LAYER Metal4 ;
        RECT  595.14 0 595.42 0.52 ;
    END
  END master_i_arsize[0]
  PIN master_i_arsize[1]
    DIRECTION OUTPUT ;
    USE SIGNAL ;
    PORT
      LAYER Metal4 ;
        RECT  553.7 0 553.98 0.52 ;
    END
  END master_i_arsize[1]
  PIN master_i_arvalid
    DIRECTION OUTPUT ;
    USE SIGNAL ;
    PORT
      LAYER Metal4 ;
        RECT  538.02 0 538.3 0.52 ;
    END
  END master_i_arvalid
  PIN master_i_awaddr[0]
    DIRECTION OUTPUT ;
    USE SIGNAL ;
    PORT
      LAYER Metal4 ;
        RECT  1690.5 0 1690.78 0.52 ;
    END
  END master_i_awaddr[0]
  PIN master_i_awaddr[10]
    DIRECTION OUTPUT ;
    USE SIGNAL ;
    PORT
      LAYER Metal4 ;
        RECT  1608.74 0 1609.02 0.52 ;
    END
  END master_i_awaddr[10]
  PIN master_i_awaddr[11]
    DIRECTION OUTPUT ;
    USE SIGNAL ;
    PORT
      LAYER Metal3 ;
        RECT  1702.655 1429.54 1703.175 1429.82 ;
    END
  END master_i_awaddr[11]
  PIN master_i_awaddr[12]
    DIRECTION OUTPUT ;
    USE SIGNAL ;
    PORT
      LAYER Metal3 ;
        RECT  1702.655 67.62 1703.175 67.9 ;
    END
  END master_i_awaddr[12]
  PIN master_i_awaddr[13]
    DIRECTION OUTPUT ;
    USE SIGNAL ;
    PORT
      LAYER Metal4 ;
        RECT  1692.74 0 1693.02 0.52 ;
    END
  END master_i_awaddr[13]
  PIN master_i_awaddr[14]
    DIRECTION OUTPUT ;
    USE SIGNAL ;
    PORT
      LAYER Metal4 ;
        RECT  1459.78 0 1460.06 0.52 ;
    END
  END master_i_awaddr[14]
  PIN master_i_awaddr[15]
    DIRECTION OUTPUT ;
    USE SIGNAL ;
    PORT
      LAYER Metal4 ;
        RECT  1643.46 0 1643.74 0.52 ;
    END
  END master_i_awaddr[15]
  PIN master_i_awaddr[16]
    DIRECTION OUTPUT ;
    USE SIGNAL ;
    PORT
      LAYER Metal3 ;
        RECT  1702.655 1610.98 1703.175 1611.26 ;
    END
  END master_i_awaddr[16]
  PIN master_i_awaddr[17]
    DIRECTION OUTPUT ;
    USE SIGNAL ;
    PORT
      LAYER Metal3 ;
        RECT  1702.655 1111.46 1703.175 1111.74 ;
    END
  END master_i_awaddr[17]
  PIN master_i_awaddr[18]
    DIRECTION OUTPUT ;
    USE SIGNAL ;
    PORT
      LAYER Metal3 ;
        RECT  1702.655 1683.78 1703.175 1684.06 ;
    END
  END master_i_awaddr[18]
  PIN master_i_awaddr[19]
    DIRECTION OUTPUT ;
    USE SIGNAL ;
    PORT
      LAYER Metal3 ;
        RECT  1702.655 199.78 1703.175 200.06 ;
    END
  END master_i_awaddr[19]
  PIN master_i_awaddr[1]
    DIRECTION OUTPUT ;
    USE SIGNAL ;
    PORT
      LAYER Metal3 ;
        RECT  1702.655 1642.34 1703.175 1642.62 ;
    END
  END master_i_awaddr[1]
  PIN master_i_awaddr[20]
    DIRECTION OUTPUT ;
    USE SIGNAL ;
    PORT
      LAYER Metal4 ;
        RECT  1693.86 0 1694.14 0.52 ;
    END
  END master_i_awaddr[20]
  PIN master_i_awaddr[21]
    DIRECTION OUTPUT ;
    USE SIGNAL ;
    PORT
      LAYER Metal4 ;
        RECT  1631.14 0 1631.42 0.52 ;
    END
  END master_i_awaddr[21]
  PIN master_i_awaddr[22]
    DIRECTION OUTPUT ;
    USE SIGNAL ;
    PORT
      LAYER Metal3 ;
        RECT  1702.655 147.14 1703.175 147.42 ;
    END
  END master_i_awaddr[22]
  PIN master_i_awaddr[23]
    DIRECTION OUTPUT ;
    USE SIGNAL ;
    PORT
      LAYER Metal3 ;
        RECT  1702.655 63.14 1703.175 63.42 ;
    END
  END master_i_awaddr[23]
  PIN master_i_awaddr[24]
    DIRECTION OUTPUT ;
    USE SIGNAL ;
    PORT
      LAYER Metal4 ;
        RECT  1442.98 0 1443.26 0.52 ;
    END
  END master_i_awaddr[24]
  PIN master_i_awaddr[25]
    DIRECTION OUTPUT ;
    USE SIGNAL ;
    PORT
      LAYER Metal3 ;
        RECT  1702.655 76.58 1703.175 76.86 ;
    END
  END master_i_awaddr[25]
  PIN master_i_awaddr[26]
    DIRECTION OUTPUT ;
    USE SIGNAL ;
    PORT
      LAYER Metal4 ;
        RECT  1624.42 1702.655 1624.7 1703.175 ;
    END
  END master_i_awaddr[26]
  PIN master_i_awaddr[27]
    DIRECTION OUTPUT ;
    USE SIGNAL ;
    PORT
      LAYER Metal4 ;
        RECT  1640.1 0 1640.38 0.52 ;
    END
  END master_i_awaddr[27]
  PIN master_i_awaddr[28]
    DIRECTION OUTPUT ;
    USE SIGNAL ;
    PORT
      LAYER Metal4 ;
        RECT  1668.1 0 1668.38 0.52 ;
    END
  END master_i_awaddr[28]
  PIN master_i_awaddr[29]
    DIRECTION OUTPUT ;
    USE SIGNAL ;
    PORT
      LAYER Metal3 ;
        RECT  1702.655 179.62 1703.175 179.9 ;
    END
  END master_i_awaddr[29]
  PIN master_i_awaddr[2]
    DIRECTION OUTPUT ;
    USE SIGNAL ;
    PORT
      LAYER Metal3 ;
        RECT  1702.655 44.1 1703.175 44.38 ;
    END
  END master_i_awaddr[2]
  PIN master_i_awaddr[30]
    DIRECTION OUTPUT ;
    USE SIGNAL ;
    PORT
      LAYER Metal3 ;
        RECT  1702.655 151.62 1703.175 151.9 ;
    END
  END master_i_awaddr[30]
  PIN master_i_awaddr[31]
    DIRECTION OUTPUT ;
    USE SIGNAL ;
    PORT
      LAYER Metal4 ;
        RECT  1645.7 0 1645.98 0.52 ;
    END
  END master_i_awaddr[31]
  PIN master_i_awaddr[3]
    DIRECTION OUTPUT ;
    USE SIGNAL ;
    PORT
      LAYER Metal3 ;
        RECT  1702.655 77.7 1703.175 77.98 ;
    END
  END master_i_awaddr[3]
  PIN master_i_awaddr[4]
    DIRECTION OUTPUT ;
    USE SIGNAL ;
    PORT
      LAYER Metal3 ;
        RECT  1702.655 123.62 1703.175 123.9 ;
    END
  END master_i_awaddr[4]
  PIN master_i_awaddr[5]
    DIRECTION OUTPUT ;
    USE SIGNAL ;
    PORT
      LAYER Metal3 ;
        RECT  1702.655 198.66 1703.175 198.94 ;
    END
  END master_i_awaddr[5]
  PIN master_i_awaddr[6]
    DIRECTION OUTPUT ;
    USE SIGNAL ;
    PORT
      LAYER Metal4 ;
        RECT  1661.38 0 1661.66 0.52 ;
    END
  END master_i_awaddr[6]
  PIN master_i_awaddr[7]
    DIRECTION OUTPUT ;
    USE SIGNAL ;
    PORT
      LAYER Metal3 ;
        RECT  1702.655 130.34 1703.175 130.62 ;
    END
  END master_i_awaddr[7]
  PIN master_i_awaddr[8]
    DIRECTION OUTPUT ;
    USE SIGNAL ;
    PORT
      LAYER Metal4 ;
        RECT  1523.62 0 1523.9 0.52 ;
    END
  END master_i_awaddr[8]
  PIN master_i_awaddr[9]
    DIRECTION OUTPUT ;
    USE SIGNAL ;
    PORT
      LAYER Metal3 ;
        RECT  1702.655 125.86 1703.175 126.14 ;
    END
  END master_i_awaddr[9]
  PIN master_i_awprot[0]
    DIRECTION OUTPUT ;
    USE SIGNAL ;
    PORT
      LAYER Metal3 ;
        RECT  1702.655 197.54 1703.175 197.82 ;
    END
  END master_i_awprot[0]
  PIN master_i_awprot[1]
    DIRECTION OUTPUT ;
    USE SIGNAL ;
    PORT
      LAYER Metal3 ;
        RECT  1702.655 1348.9 1703.175 1349.18 ;
    END
  END master_i_awprot[1]
  PIN master_i_awprot[2]
    DIRECTION OUTPUT ;
    USE SIGNAL ;
    PORT
      LAYER Metal3 ;
        RECT  1702.655 64.26 1703.175 64.54 ;
    END
  END master_i_awprot[2]
  PIN master_i_awsize[0]
    DIRECTION OUTPUT ;
    USE SIGNAL ;
    PORT
      LAYER Metal3 ;
        RECT  1702.655 1668.1 1703.175 1668.38 ;
    END
  END master_i_awsize[0]
  PIN master_i_awsize[1]
    DIRECTION OUTPUT ;
    USE SIGNAL ;
    PORT
      LAYER Metal4 ;
        RECT  1691.62 0 1691.9 0.52 ;
    END
  END master_i_awsize[1]
  PIN master_i_awvalid
    DIRECTION OUTPUT ;
    USE SIGNAL ;
    PORT
      LAYER Metal4 ;
        RECT  1669.22 0 1669.5 0.52 ;
    END
  END master_i_awvalid
  PIN master_i_bready
    DIRECTION OUTPUT ;
    USE SIGNAL ;
    PORT
      LAYER Metal3 ;
        RECT  0 583.94 0.52 584.22 ;
    END
  END master_i_bready
  PIN master_i_m_arready_arready
    DIRECTION INPUT ;
    USE SIGNAL ;
    PORT
      LAYER Metal4 ;
        RECT  563.78 0 564.06 0.52 ;
    END
  END master_i_m_arready_arready
  PIN master_i_m_awready_awready
    DIRECTION INPUT ;
    USE SIGNAL ;
    PORT
      LAYER Metal4 ;
        RECT  1.54 0 1.82 0.52 ;
    END
  END master_i_m_awready_awready
  PIN master_i_m_bvalid_bresp[0]
    DIRECTION INPUT ;
    USE SIGNAL ;
    PORT
      LAYER Metal4 ;
        RECT  2.66 0 2.94 0.52 ;
    END
  END master_i_m_bvalid_bresp[0]
  PIN master_i_m_bvalid_bresp[1]
    DIRECTION INPUT ;
    USE SIGNAL ;
    PORT
      LAYER Metal4 ;
        RECT  3.78 0 4.06 0.52 ;
    END
  END master_i_m_bvalid_bresp[1]
  PIN master_i_m_bvalid_bvalid
    DIRECTION INPUT ;
    USE SIGNAL ;
    PORT
      LAYER Metal3 ;
        RECT  0 585.06 0.52 585.34 ;
    END
  END master_i_m_bvalid_bvalid
  PIN master_i_m_rvalid_rdata[0]
    DIRECTION INPUT ;
    USE SIGNAL ;
    PORT
      LAYER Metal3 ;
        RECT  0 131.46 0.52 131.74 ;
    END
  END master_i_m_rvalid_rdata[0]
  PIN master_i_m_rvalid_rdata[10]
    DIRECTION INPUT ;
    USE SIGNAL ;
    PORT
      LAYER Metal3 ;
        RECT  0 121.38 0.52 121.66 ;
    END
  END master_i_m_rvalid_rdata[10]
  PIN master_i_m_rvalid_rdata[11]
    DIRECTION INPUT ;
    USE SIGNAL ;
    PORT
      LAYER Metal3 ;
        RECT  0 54.18 0.52 54.46 ;
    END
  END master_i_m_rvalid_rdata[11]
  PIN master_i_m_rvalid_rdata[12]
    DIRECTION INPUT ;
    USE SIGNAL ;
    PORT
      LAYER Metal3 ;
        RECT  0 103.46 0.52 103.74 ;
    END
  END master_i_m_rvalid_rdata[12]
  PIN master_i_m_rvalid_rdata[13]
    DIRECTION INPUT ;
    USE SIGNAL ;
    PORT
      LAYER Metal3 ;
        RECT  0 69.86 0.52 70.14 ;
    END
  END master_i_m_rvalid_rdata[13]
  PIN master_i_m_rvalid_rdata[14]
    DIRECTION INPUT ;
    USE SIGNAL ;
    PORT
      LAYER Metal4 ;
        RECT  85.54 0 85.82 0.52 ;
    END
  END master_i_m_rvalid_rdata[14]
  PIN master_i_m_rvalid_rdata[15]
    DIRECTION INPUT ;
    USE SIGNAL ;
    PORT
      LAYER Metal4 ;
        RECT  60.9 0 61.18 0.52 ;
    END
  END master_i_m_rvalid_rdata[15]
  PIN master_i_m_rvalid_rdata[16]
    DIRECTION INPUT ;
    USE SIGNAL ;
    PORT
      LAYER Metal4 ;
        RECT  94.5 0 94.78 0.52 ;
    END
  END master_i_m_rvalid_rdata[16]
  PIN master_i_m_rvalid_rdata[17]
    DIRECTION INPUT ;
    USE SIGNAL ;
    PORT
      LAYER Metal3 ;
        RECT  0 95.62 0.52 95.9 ;
    END
  END master_i_m_rvalid_rdata[17]
  PIN master_i_m_rvalid_rdata[18]
    DIRECTION INPUT ;
    USE SIGNAL ;
    PORT
      LAYER Metal3 ;
        RECT  0 120.26 0.52 120.54 ;
    END
  END master_i_m_rvalid_rdata[18]
  PIN master_i_m_rvalid_rdata[19]
    DIRECTION INPUT ;
    USE SIGNAL ;
    PORT
      LAYER Metal4 ;
        RECT  67.62 0 67.9 0.52 ;
    END
  END master_i_m_rvalid_rdata[19]
  PIN master_i_m_rvalid_rdata[1]
    DIRECTION INPUT ;
    USE SIGNAL ;
    PORT
      LAYER Metal4 ;
        RECT  110.18 0 110.46 0.52 ;
    END
  END master_i_m_rvalid_rdata[1]
  PIN master_i_m_rvalid_rdata[20]
    DIRECTION INPUT ;
    USE SIGNAL ;
    PORT
      LAYER Metal4 ;
        RECT  92.26 0 92.54 0.52 ;
    END
  END master_i_m_rvalid_rdata[20]
  PIN master_i_m_rvalid_rdata[21]
    DIRECTION INPUT ;
    USE SIGNAL ;
    PORT
      LAYER Metal4 ;
        RECT  93.38 0 93.66 0.52 ;
    END
  END master_i_m_rvalid_rdata[21]
  PIN master_i_m_rvalid_rdata[22]
    DIRECTION INPUT ;
    USE SIGNAL ;
    PORT
      LAYER Metal4 ;
        RECT  95.62 0 95.9 0.52 ;
    END
  END master_i_m_rvalid_rdata[22]
  PIN master_i_m_rvalid_rdata[23]
    DIRECTION INPUT ;
    USE SIGNAL ;
    PORT
      LAYER Metal4 ;
        RECT  128.1 0 128.38 0.52 ;
    END
  END master_i_m_rvalid_rdata[23]
  PIN master_i_m_rvalid_rdata[24]
    DIRECTION INPUT ;
    USE SIGNAL ;
    PORT
      LAYER Metal4 ;
        RECT  122.5 0 122.78 0.52 ;
    END
  END master_i_m_rvalid_rdata[24]
  PIN master_i_m_rvalid_rdata[25]
    DIRECTION INPUT ;
    USE SIGNAL ;
    PORT
      LAYER Metal4 ;
        RECT  148.26 0 148.54 0.52 ;
    END
  END master_i_m_rvalid_rdata[25]
  PIN master_i_m_rvalid_rdata[26]
    DIRECTION INPUT ;
    USE SIGNAL ;
    PORT
      LAYER Metal4 ;
        RECT  146.02 0 146.3 0.52 ;
    END
  END master_i_m_rvalid_rdata[26]
  PIN master_i_m_rvalid_rdata[27]
    DIRECTION INPUT ;
    USE SIGNAL ;
    PORT
      LAYER Metal4 ;
        RECT  121.38 0 121.66 0.52 ;
    END
  END master_i_m_rvalid_rdata[27]
  PIN master_i_m_rvalid_rdata[28]
    DIRECTION INPUT ;
    USE SIGNAL ;
    PORT
      LAYER Metal4 ;
        RECT  123.62 0 123.9 0.52 ;
    END
  END master_i_m_rvalid_rdata[28]
  PIN master_i_m_rvalid_rdata[29]
    DIRECTION INPUT ;
    USE SIGNAL ;
    PORT
      LAYER Metal4 ;
        RECT  147.14 0 147.42 0.52 ;
    END
  END master_i_m_rvalid_rdata[29]
  PIN master_i_m_rvalid_rdata[2]
    DIRECTION INPUT ;
    USE SIGNAL ;
    PORT
      LAYER Metal3 ;
        RECT  0 132.58 0.52 132.86 ;
    END
  END master_i_m_rvalid_rdata[2]
  PIN master_i_m_rvalid_rdata[30]
    DIRECTION INPUT ;
    USE SIGNAL ;
    PORT
      LAYER Metal4 ;
        RECT  149.38 0 149.66 0.52 ;
    END
  END master_i_m_rvalid_rdata[30]
  PIN master_i_m_rvalid_rdata[31]
    DIRECTION INPUT ;
    USE SIGNAL ;
    PORT
      LAYER Metal4 ;
        RECT  156.1 0 156.38 0.52 ;
    END
  END master_i_m_rvalid_rdata[31]
  PIN master_i_m_rvalid_rdata[3]
    DIRECTION INPUT ;
    USE SIGNAL ;
    PORT
      LAYER Metal3 ;
        RECT  0 48.58 0.52 48.86 ;
    END
  END master_i_m_rvalid_rdata[3]
  PIN master_i_m_rvalid_rdata[4]
    DIRECTION INPUT ;
    USE SIGNAL ;
    PORT
      LAYER Metal3 ;
        RECT  0 79.94 0.52 80.22 ;
    END
  END master_i_m_rvalid_rdata[4]
  PIN master_i_m_rvalid_rdata[5]
    DIRECTION INPUT ;
    USE SIGNAL ;
    PORT
      LAYER Metal3 ;
        RECT  0 70.98 0.52 71.26 ;
    END
  END master_i_m_rvalid_rdata[5]
  PIN master_i_m_rvalid_rdata[6]
    DIRECTION INPUT ;
    USE SIGNAL ;
    PORT
      LAYER Metal3 ;
        RECT  0 30.66 0.52 30.94 ;
    END
  END master_i_m_rvalid_rdata[6]
  PIN master_i_m_rvalid_rdata[7]
    DIRECTION INPUT ;
    USE SIGNAL ;
    PORT
      LAYER Metal3 ;
        RECT  0 26.18 0.52 26.46 ;
    END
  END master_i_m_rvalid_rdata[7]
  PIN master_i_m_rvalid_rdata[8]
    DIRECTION INPUT ;
    USE SIGNAL ;
    PORT
      LAYER Metal3 ;
        RECT  0 126.98 0.52 127.26 ;
    END
  END master_i_m_rvalid_rdata[8]
  PIN master_i_m_rvalid_rdata[9]
    DIRECTION INPUT ;
    USE SIGNAL ;
    PORT
      LAYER Metal3 ;
        RECT  0 96.74 0.52 97.02 ;
    END
  END master_i_m_rvalid_rdata[9]
  PIN master_i_m_rvalid_rresp[0]
    DIRECTION INPUT ;
    USE SIGNAL ;
    PORT
      LAYER Metal4 ;
        RECT  144.9 0 145.18 0.52 ;
    END
  END master_i_m_rvalid_rresp[0]
  PIN master_i_m_rvalid_rresp[1]
    DIRECTION INPUT ;
    USE SIGNAL ;
    PORT
      LAYER Metal4 ;
        RECT  111.3 0 111.58 0.52 ;
    END
  END master_i_m_rvalid_rresp[1]
  PIN master_i_m_rvalid_rvalid
    DIRECTION INPUT ;
    USE SIGNAL ;
    PORT
      LAYER Metal3 ;
        RECT  0 133.7 0.52 133.98 ;
    END
  END master_i_m_rvalid_rvalid
  PIN master_i_m_wready_wready
    DIRECTION INPUT ;
    USE SIGNAL ;
    PORT
      LAYER Metal4 ;
        RECT  4.9 0 5.18 0.52 ;
    END
  END master_i_m_wready_wready
  PIN master_i_rready
    DIRECTION OUTPUT ;
    USE SIGNAL ;
    PORT
      LAYER Metal3 ;
        RECT  0 176.26 0.52 176.54 ;
    END
  END master_i_rready
  PIN master_i_wdata[0]
    DIRECTION OUTPUT ;
    USE SIGNAL ;
    PORT
      LAYER Metal4 ;
        RECT  1645.7 1702.655 1645.98 1703.175 ;
    END
  END master_i_wdata[0]
  PIN master_i_wdata[10]
    DIRECTION OUTPUT ;
    USE SIGNAL ;
    PORT
      LAYER Metal4 ;
        RECT  1662.5 0 1662.78 0.52 ;
    END
  END master_i_wdata[10]
  PIN master_i_wdata[11]
    DIRECTION OUTPUT ;
    USE SIGNAL ;
    PORT
      LAYER Metal4 ;
        RECT  1632.26 0 1632.54 0.52 ;
    END
  END master_i_wdata[11]
  PIN master_i_wdata[12]
    DIRECTION OUTPUT ;
    USE SIGNAL ;
    PORT
      LAYER Metal3 ;
        RECT  1702.655 122.5 1703.175 122.78 ;
    END
  END master_i_wdata[12]
  PIN master_i_wdata[13]
    DIRECTION OUTPUT ;
    USE SIGNAL ;
    PORT
      LAYER Metal4 ;
        RECT  1609.86 0 1610.14 0.52 ;
    END
  END master_i_wdata[13]
  PIN master_i_wdata[14]
    DIRECTION OUTPUT ;
    USE SIGNAL ;
    PORT
      LAYER Metal4 ;
        RECT  1670.34 0 1670.62 0.52 ;
    END
  END master_i_wdata[14]
  PIN master_i_wdata[15]
    DIRECTION OUTPUT ;
    USE SIGNAL ;
    PORT
      LAYER Metal3 ;
        RECT  1702.655 1687.14 1703.175 1687.42 ;
    END
  END master_i_wdata[15]
  PIN master_i_wdata[16]
    DIRECTION OUTPUT ;
    USE SIGNAL ;
    PORT
      LAYER Metal3 ;
        RECT  1702.655 91.14 1703.175 91.42 ;
    END
  END master_i_wdata[16]
  PIN master_i_wdata[17]
    DIRECTION OUTPUT ;
    USE SIGNAL ;
    PORT
      LAYER Metal4 ;
        RECT  1660.26 0 1660.54 0.52 ;
    END
  END master_i_wdata[17]
  PIN master_i_wdata[18]
    DIRECTION OUTPUT ;
    USE SIGNAL ;
    PORT
      LAYER Metal3 ;
        RECT  1702.655 93.38 1703.175 93.66 ;
    END
  END master_i_wdata[18]
  PIN master_i_wdata[19]
    DIRECTION OUTPUT ;
    USE SIGNAL ;
    PORT
      LAYER Metal4 ;
        RECT  1570.66 0 1570.94 0.52 ;
    END
  END master_i_wdata[19]
  PIN master_i_wdata[1]
    DIRECTION OUTPUT ;
    USE SIGNAL ;
    PORT
      LAYER Metal3 ;
        RECT  1702.655 1688.26 1703.175 1688.54 ;
    END
  END master_i_wdata[1]
  PIN master_i_wdata[20]
    DIRECTION OUTPUT ;
    USE SIGNAL ;
    PORT
      LAYER Metal3 ;
        RECT  1702.655 1627.78 1703.175 1628.06 ;
    END
  END master_i_wdata[20]
  PIN master_i_wdata[21]
    DIRECTION OUTPUT ;
    USE SIGNAL ;
    PORT
      LAYER Metal3 ;
        RECT  1702.655 90.02 1703.175 90.3 ;
    END
  END master_i_wdata[21]
  PIN master_i_wdata[22]
    DIRECTION OUTPUT ;
    USE SIGNAL ;
    PORT
      LAYER Metal3 ;
        RECT  1702.655 165.06 1703.175 165.34 ;
    END
  END master_i_wdata[22]
  PIN master_i_wdata[23]
    DIRECTION OUTPUT ;
    USE SIGNAL ;
    PORT
      LAYER Metal3 ;
        RECT  1702.655 94.5 1703.175 94.78 ;
    END
  END master_i_wdata[23]
  PIN master_i_wdata[24]
    DIRECTION OUTPUT ;
    USE SIGNAL ;
    PORT
      LAYER Metal3 ;
        RECT  1702.655 1637.86 1703.175 1638.14 ;
    END
  END master_i_wdata[24]
  PIN master_i_wdata[25]
    DIRECTION OUTPUT ;
    USE SIGNAL ;
    PORT
      LAYER Metal3 ;
        RECT  1702.655 149.38 1703.175 149.66 ;
    END
  END master_i_wdata[25]
  PIN master_i_wdata[26]
    DIRECTION OUTPUT ;
    USE SIGNAL ;
    PORT
      LAYER Metal4 ;
        RECT  1672.58 0 1672.86 0.52 ;
    END
  END master_i_wdata[26]
  PIN master_i_wdata[27]
    DIRECTION OUTPUT ;
    USE SIGNAL ;
    PORT
      LAYER Metal3 ;
        RECT  1702.655 206.5 1703.175 206.78 ;
    END
  END master_i_wdata[27]
  PIN master_i_wdata[28]
    DIRECTION OUTPUT ;
    USE SIGNAL ;
    PORT
      LAYER Metal3 ;
        RECT  1702.655 75.46 1703.175 75.74 ;
    END
  END master_i_wdata[28]
  PIN master_i_wdata[29]
    DIRECTION OUTPUT ;
    USE SIGNAL ;
    PORT
      LAYER Metal3 ;
        RECT  1702.655 150.5 1703.175 150.78 ;
    END
  END master_i_wdata[29]
  PIN master_i_wdata[2]
    DIRECTION OUTPUT ;
    USE SIGNAL ;
    PORT
      LAYER Metal3 ;
        RECT  1702.655 109.06 1703.175 109.34 ;
    END
  END master_i_wdata[2]
  PIN master_i_wdata[30]
    DIRECTION OUTPUT ;
    USE SIGNAL ;
    PORT
      LAYER Metal3 ;
        RECT  1702.655 1621.06 1703.175 1621.34 ;
    END
  END master_i_wdata[30]
  PIN master_i_wdata[31]
    DIRECTION OUTPUT ;
    USE SIGNAL ;
    PORT
      LAYER Metal3 ;
        RECT  1702.655 1664.74 1703.175 1665.02 ;
    END
  END master_i_wdata[31]
  PIN master_i_wdata[3]
    DIRECTION OUTPUT ;
    USE SIGNAL ;
    PORT
      LAYER Metal3 ;
        RECT  1702.655 175.14 1703.175 175.42 ;
    END
  END master_i_wdata[3]
  PIN master_i_wdata[4]
    DIRECTION OUTPUT ;
    USE SIGNAL ;
    PORT
      LAYER Metal4 ;
        RECT  1441.86 0 1442.14 0.52 ;
    END
  END master_i_wdata[4]
  PIN master_i_wdata[5]
    DIRECTION OUTPUT ;
    USE SIGNAL ;
    PORT
      LAYER Metal4 ;
        RECT  1614.34 0 1614.62 0.52 ;
    END
  END master_i_wdata[5]
  PIN master_i_wdata[6]
    DIRECTION OUTPUT ;
    USE SIGNAL ;
    PORT
      LAYER Metal4 ;
        RECT  1628.9 0 1629.18 0.52 ;
    END
  END master_i_wdata[6]
  PIN master_i_wdata[7]
    DIRECTION OUTPUT ;
    USE SIGNAL ;
    PORT
      LAYER Metal4 ;
        RECT  1445.22 0 1445.5 0.52 ;
    END
  END master_i_wdata[7]
  PIN master_i_wdata[8]
    DIRECTION OUTPUT ;
    USE SIGNAL ;
    PORT
      LAYER Metal4 ;
        RECT  1646.82 0 1647.1 0.52 ;
    END
  END master_i_wdata[8]
  PIN master_i_wdata[9]
    DIRECTION OUTPUT ;
    USE SIGNAL ;
    PORT
      LAYER Metal3 ;
        RECT  1702.655 124.74 1703.175 125.02 ;
    END
  END master_i_wdata[9]
  PIN master_i_wstrb[0]
    DIRECTION OUTPUT ;
    USE SIGNAL ;
    PORT
      LAYER Metal3 ;
        RECT  1702.655 70.98 1703.175 71.26 ;
    END
  END master_i_wstrb[0]
  PIN master_i_wstrb[1]
    DIRECTION OUTPUT ;
    USE SIGNAL ;
    PORT
      LAYER Metal3 ;
        RECT  1702.655 40.74 1703.175 41.02 ;
    END
  END master_i_wstrb[1]
  PIN master_i_wstrb[2]
    DIRECTION OUTPUT ;
    USE SIGNAL ;
    PORT
      LAYER Metal4 ;
        RECT  1637.86 0 1638.14 0.52 ;
    END
  END master_i_wstrb[2]
  PIN master_i_wstrb[3]
    DIRECTION OUTPUT ;
    USE SIGNAL ;
    PORT
      LAYER Metal4 ;
        RECT  1569.54 0 1569.82 0.52 ;
    END
  END master_i_wstrb[3]
  PIN master_i_wvalid
    DIRECTION OUTPUT ;
    USE SIGNAL ;
    PORT
      LAYER Metal3 ;
        RECT  1702.655 107.94 1703.175 108.22 ;
    END
  END master_i_wvalid
  PIN resetpc[0]
    DIRECTION INPUT ;
    USE SIGNAL ;
    PORT
      LAYER Metal4 ;
        RECT  673.54 0 673.82 0.52 ;
    END
  END resetpc[0]
  PIN resetpc[10]
    DIRECTION INPUT ;
    USE SIGNAL ;
    PORT
      LAYER Metal4 ;
        RECT  620.9 0 621.18 0.52 ;
    END
  END resetpc[10]
  PIN resetpc[11]
    DIRECTION INPUT ;
    USE SIGNAL ;
    PORT
      LAYER Metal4 ;
        RECT  718.34 0 718.62 0.52 ;
    END
  END resetpc[11]
  PIN resetpc[12]
    DIRECTION INPUT ;
    USE SIGNAL ;
    PORT
      LAYER Metal4 ;
        RECT  738.5 0 738.78 0.52 ;
    END
  END resetpc[12]
  PIN resetpc[13]
    DIRECTION INPUT ;
    USE SIGNAL ;
    PORT
      LAYER Metal4 ;
        RECT  726.18 0 726.46 0.52 ;
    END
  END resetpc[13]
  PIN resetpc[14]
    DIRECTION INPUT ;
    USE SIGNAL ;
    PORT
      LAYER Metal4 ;
        RECT  582.82 0 583.1 0.52 ;
    END
  END resetpc[14]
  PIN resetpc[15]
    DIRECTION INPUT ;
    USE SIGNAL ;
    PORT
      LAYER Metal4 ;
        RECT  597.38 0 597.66 0.52 ;
    END
  END resetpc[15]
  PIN resetpc[16]
    DIRECTION INPUT ;
    USE SIGNAL ;
    PORT
      LAYER Metal4 ;
        RECT  654.5 0 654.78 0.52 ;
    END
  END resetpc[16]
  PIN resetpc[17]
    DIRECTION INPUT ;
    USE SIGNAL ;
    PORT
      LAYER Metal4 ;
        RECT  564.9 0 565.18 0.52 ;
    END
  END resetpc[17]
  PIN resetpc[18]
    DIRECTION INPUT ;
    USE SIGNAL ;
    PORT
      LAYER Metal4 ;
        RECT  589.54 0 589.82 0.52 ;
    END
  END resetpc[18]
  PIN resetpc[19]
    DIRECTION INPUT ;
    USE SIGNAL ;
    PORT
      LAYER Metal4 ;
        RECT  557.06 0 557.34 0.52 ;
    END
  END resetpc[19]
  PIN resetpc[1]
    DIRECTION INPUT ;
    USE SIGNAL ;
    PORT
      LAYER Metal4 ;
        RECT  674.66 0 674.94 0.52 ;
    END
  END resetpc[1]
  PIN resetpc[20]
    DIRECTION INPUT ;
    USE SIGNAL ;
    PORT
      LAYER Metal4 ;
        RECT  577.22 0 577.5 0.52 ;
    END
  END resetpc[20]
  PIN resetpc[21]
    DIRECTION INPUT ;
    USE SIGNAL ;
    PORT
      LAYER Metal4 ;
        RECT  555.94 0 556.22 0.52 ;
    END
  END resetpc[21]
  PIN resetpc[22]
    DIRECTION INPUT ;
    USE SIGNAL ;
    PORT
      LAYER Metal4 ;
        RECT  554.82 0 555.1 0.52 ;
    END
  END resetpc[22]
  PIN resetpc[23]
    DIRECTION INPUT ;
    USE SIGNAL ;
    PORT
      LAYER Metal4 ;
        RECT  591.78 0 592.06 0.52 ;
    END
  END resetpc[23]
  PIN resetpc[24]
    DIRECTION INPUT ;
    USE SIGNAL ;
    PORT
      LAYER Metal4 ;
        RECT  570.5 0 570.78 0.52 ;
    END
  END resetpc[24]
  PIN resetpc[25]
    DIRECTION INPUT ;
    USE SIGNAL ;
    PORT
      LAYER Metal4 ;
        RECT  652.26 0 652.54 0.52 ;
    END
  END resetpc[25]
  PIN resetpc[26]
    DIRECTION INPUT ;
    USE SIGNAL ;
    PORT
      LAYER Metal4 ;
        RECT  590.66 0 590.94 0.52 ;
    END
  END resetpc[26]
  PIN resetpc[27]
    DIRECTION INPUT ;
    USE SIGNAL ;
    PORT
      LAYER Metal4 ;
        RECT  587.3 0 587.58 0.52 ;
    END
  END resetpc[27]
  PIN resetpc[28]
    DIRECTION INPUT ;
    USE SIGNAL ;
    PORT
      LAYER Metal4 ;
        RECT  622.02 0 622.3 0.52 ;
    END
  END resetpc[28]
  PIN resetpc[29]
    DIRECTION INPUT ;
    USE SIGNAL ;
    PORT
      LAYER Metal4 ;
        RECT  616.42 0 616.7 0.52 ;
    END
  END resetpc[29]
  PIN resetpc[2]
    DIRECTION INPUT ;
    USE SIGNAL ;
    PORT
      LAYER Metal4 ;
        RECT  655.62 0 655.9 0.52 ;
    END
  END resetpc[2]
  PIN resetpc[30]
    DIRECTION INPUT ;
    USE SIGNAL ;
    PORT
      LAYER Metal4 ;
        RECT  691.46 0 691.74 0.52 ;
    END
  END resetpc[30]
  PIN resetpc[31]
    DIRECTION INPUT ;
    USE SIGNAL ;
    PORT
      LAYER Metal4 ;
        RECT  573.86 0 574.14 0.52 ;
    END
  END resetpc[31]
  PIN resetpc[3]
    DIRECTION INPUT ;
    USE SIGNAL ;
    PORT
      LAYER Metal3 ;
        RECT  0 672.42 0.52 672.7 ;
    END
  END resetpc[3]
  PIN resetpc[4]
    DIRECTION INPUT ;
    USE SIGNAL ;
    PORT
      LAYER Metal4 ;
        RECT  638.82 0 639.1 0.52 ;
    END
  END resetpc[4]
  PIN resetpc[5]
    DIRECTION INPUT ;
    USE SIGNAL ;
    PORT
      LAYER Metal4 ;
        RECT  791.14 0 791.42 0.52 ;
    END
  END resetpc[5]
  PIN resetpc[6]
    DIRECTION INPUT ;
    USE SIGNAL ;
    PORT
      LAYER Metal4 ;
        RECT  643.3 0 643.58 0.52 ;
    END
  END resetpc[6]
  PIN resetpc[7]
    DIRECTION INPUT ;
    USE SIGNAL ;
    PORT
      LAYER Metal3 ;
        RECT  0 671.3 0.52 671.58 ;
    END
  END resetpc[7]
  PIN resetpc[8]
    DIRECTION INPUT ;
    USE SIGNAL ;
    PORT
      LAYER Metal4 ;
        RECT  613.06 0 613.34 0.52 ;
    END
  END resetpc[8]
  PIN resetpc[9]
    DIRECTION INPUT ;
    USE SIGNAL ;
    PORT
      LAYER Metal4 ;
        RECT  730.66 0 730.94 0.52 ;
    END
  END resetpc[9]
  PIN sb_clint_msip_put
    DIRECTION INPUT ;
    USE SIGNAL ;
    PORT
      LAYER Metal4 ;
        RECT  897.54 1702.655 897.82 1703.175 ;
    END
  END sb_clint_msip_put
  PIN sb_clint_mtime_put[0]
    DIRECTION INPUT ;
    USE SIGNAL ;
    PORT
      LAYER Metal4 ;
        RECT  971.46 1702.655 971.74 1703.175 ;
    END
  END sb_clint_mtime_put[0]
  PIN sb_clint_mtime_put[10]
    DIRECTION INPUT ;
    USE SIGNAL ;
    PORT
      LAYER Metal3 ;
        RECT  0 1193.22 0.52 1193.5 ;
    END
  END sb_clint_mtime_put[10]
  PIN sb_clint_mtime_put[11]
    DIRECTION INPUT ;
    USE SIGNAL ;
    PORT
      LAYER Metal4 ;
        RECT  419.3 1702.655 419.58 1703.175 ;
    END
  END sb_clint_mtime_put[11]
  PIN sb_clint_mtime_put[12]
    DIRECTION INPUT ;
    USE SIGNAL ;
    PORT
      LAYER Metal3 ;
        RECT  0 1194.34 0.52 1194.62 ;
    END
  END sb_clint_mtime_put[12]
  PIN sb_clint_mtime_put[13]
    DIRECTION INPUT ;
    USE SIGNAL ;
    PORT
      LAYER Metal3 ;
        RECT  0 1241.38 0.52 1241.66 ;
    END
  END sb_clint_mtime_put[13]
  PIN sb_clint_mtime_put[14]
    DIRECTION INPUT ;
    USE SIGNAL ;
    PORT
      LAYER Metal3 ;
        RECT  0 1103.62 0.52 1103.9 ;
    END
  END sb_clint_mtime_put[14]
  PIN sb_clint_mtime_put[15]
    DIRECTION INPUT ;
    USE SIGNAL ;
    PORT
      LAYER Metal3 ;
        RECT  0 1146.18 0.52 1146.46 ;
    END
  END sb_clint_mtime_put[15]
  PIN sb_clint_mtime_put[16]
    DIRECTION INPUT ;
    USE SIGNAL ;
    PORT
      LAYER Metal3 ;
        RECT  0 1226.82 0.52 1227.1 ;
    END
  END sb_clint_mtime_put[16]
  PIN sb_clint_mtime_put[17]
    DIRECTION INPUT ;
    USE SIGNAL ;
    PORT
      LAYER Metal3 ;
        RECT  0 1121.54 0.52 1121.82 ;
    END
  END sb_clint_mtime_put[17]
  PIN sb_clint_mtime_put[18]
    DIRECTION INPUT ;
    USE SIGNAL ;
    PORT
      LAYER Metal3 ;
        RECT  0 1156.26 0.52 1156.54 ;
    END
  END sb_clint_mtime_put[18]
  PIN sb_clint_mtime_put[19]
    DIRECTION INPUT ;
    USE SIGNAL ;
    PORT
      LAYER Metal3 ;
        RECT  0 1182.02 0.52 1182.3 ;
    END
  END sb_clint_mtime_put[19]
  PIN sb_clint_mtime_put[1]
    DIRECTION INPUT ;
    USE SIGNAL ;
    PORT
      LAYER Metal4 ;
        RECT  405.86 1702.655 406.14 1703.175 ;
    END
  END sb_clint_mtime_put[1]
  PIN sb_clint_mtime_put[20]
    DIRECTION INPUT ;
    USE SIGNAL ;
    PORT
      LAYER Metal3 ;
        RECT  0 1168.58 0.52 1168.86 ;
    END
  END sb_clint_mtime_put[20]
  PIN sb_clint_mtime_put[21]
    DIRECTION INPUT ;
    USE SIGNAL ;
    PORT
      LAYER Metal3 ;
        RECT  0 1129.38 0.52 1129.66 ;
    END
  END sb_clint_mtime_put[21]
  PIN sb_clint_mtime_put[22]
    DIRECTION INPUT ;
    USE SIGNAL ;
    PORT
      LAYER Metal3 ;
        RECT  0 1215.62 0.52 1215.9 ;
    END
  END sb_clint_mtime_put[22]
  PIN sb_clint_mtime_put[23]
    DIRECTION INPUT ;
    USE SIGNAL ;
    PORT
      LAYER Metal3 ;
        RECT  0 1235.78 0.52 1236.06 ;
    END
  END sb_clint_mtime_put[23]
  PIN sb_clint_mtime_put[24]
    DIRECTION INPUT ;
    USE SIGNAL ;
    PORT
      LAYER Metal3 ;
        RECT  0 1203.3 0.52 1203.58 ;
    END
  END sb_clint_mtime_put[24]
  PIN sb_clint_mtime_put[25]
    DIRECTION INPUT ;
    USE SIGNAL ;
    PORT
      LAYER Metal3 ;
        RECT  0 1195.46 0.52 1195.74 ;
    END
  END sb_clint_mtime_put[25]
  PIN sb_clint_mtime_put[26]
    DIRECTION INPUT ;
    USE SIGNAL ;
    PORT
      LAYER Metal3 ;
        RECT  0 1229.06 0.52 1229.34 ;
    END
  END sb_clint_mtime_put[26]
  PIN sb_clint_mtime_put[27]
    DIRECTION INPUT ;
    USE SIGNAL ;
    PORT
      LAYER Metal3 ;
        RECT  0 1216.74 0.52 1217.02 ;
    END
  END sb_clint_mtime_put[27]
  PIN sb_clint_mtime_put[28]
    DIRECTION INPUT ;
    USE SIGNAL ;
    PORT
      LAYER Metal4 ;
        RECT  611.94 1702.655 612.22 1703.175 ;
    END
  END sb_clint_mtime_put[28]
  PIN sb_clint_mtime_put[29]
    DIRECTION INPUT ;
    USE SIGNAL ;
    PORT
      LAYER Metal4 ;
        RECT  480.9 1702.655 481.18 1703.175 ;
    END
  END sb_clint_mtime_put[29]
  PIN sb_clint_mtime_put[2]
    DIRECTION INPUT ;
    USE SIGNAL ;
    PORT
      LAYER Metal4 ;
        RECT  974.82 1702.655 975.1 1703.175 ;
    END
  END sb_clint_mtime_put[2]
  PIN sb_clint_mtime_put[30]
    DIRECTION INPUT ;
    USE SIGNAL ;
    PORT
      LAYER Metal4 ;
        RECT  530.18 1702.655 530.46 1703.175 ;
    END
  END sb_clint_mtime_put[30]
  PIN sb_clint_mtime_put[31]
    DIRECTION INPUT ;
    USE SIGNAL ;
    PORT
      LAYER Metal4 ;
        RECT  515.62 1702.655 515.9 1703.175 ;
    END
  END sb_clint_mtime_put[31]
  PIN sb_clint_mtime_put[32]
    DIRECTION INPUT ;
    USE SIGNAL ;
    PORT
      LAYER Metal4 ;
        RECT  617.54 1702.655 617.82 1703.175 ;
    END
  END sb_clint_mtime_put[32]
  PIN sb_clint_mtime_put[33]
    DIRECTION INPUT ;
    USE SIGNAL ;
    PORT
      LAYER Metal4 ;
        RECT  1093.54 1702.655 1093.82 1703.175 ;
    END
  END sb_clint_mtime_put[33]
  PIN sb_clint_mtime_put[34]
    DIRECTION INPUT ;
    USE SIGNAL ;
    PORT
      LAYER Metal4 ;
        RECT  1095.78 1702.655 1096.06 1703.175 ;
    END
  END sb_clint_mtime_put[34]
  PIN sb_clint_mtime_put[35]
    DIRECTION INPUT ;
    USE SIGNAL ;
    PORT
      LAYER Metal4 ;
        RECT  1094.66 1702.655 1094.94 1703.175 ;
    END
  END sb_clint_mtime_put[35]
  PIN sb_clint_mtime_put[36]
    DIRECTION INPUT ;
    USE SIGNAL ;
    PORT
      LAYER Metal4 ;
        RECT  1101.38 1702.655 1101.66 1703.175 ;
    END
  END sb_clint_mtime_put[36]
  PIN sb_clint_mtime_put[37]
    DIRECTION INPUT ;
    USE SIGNAL ;
    PORT
      LAYER Metal4 ;
        RECT  1096.9 1702.655 1097.18 1703.175 ;
    END
  END sb_clint_mtime_put[37]
  PIN sb_clint_mtime_put[38]
    DIRECTION INPUT ;
    USE SIGNAL ;
    PORT
      LAYER Metal4 ;
        RECT  913.22 1702.655 913.5 1703.175 ;
    END
  END sb_clint_mtime_put[38]
  PIN sb_clint_mtime_put[39]
    DIRECTION INPUT ;
    USE SIGNAL ;
    PORT
      LAYER Metal4 ;
        RECT  906.5 1702.655 906.78 1703.175 ;
    END
  END sb_clint_mtime_put[39]
  PIN sb_clint_mtime_put[3]
    DIRECTION INPUT ;
    USE SIGNAL ;
    PORT
      LAYER Metal4 ;
        RECT  1014.02 1702.655 1014.3 1703.175 ;
    END
  END sb_clint_mtime_put[3]
  PIN sb_clint_mtime_put[40]
    DIRECTION INPUT ;
    USE SIGNAL ;
    PORT
      LAYER Metal4 ;
        RECT  785.54 1702.655 785.82 1703.175 ;
    END
  END sb_clint_mtime_put[40]
  PIN sb_clint_mtime_put[41]
    DIRECTION INPUT ;
    USE SIGNAL ;
    PORT
      LAYER Metal4 ;
        RECT  792.26 1702.655 792.54 1703.175 ;
    END
  END sb_clint_mtime_put[41]
  PIN sb_clint_mtime_put[42]
    DIRECTION INPUT ;
    USE SIGNAL ;
    PORT
      LAYER Metal4 ;
        RECT  784.42 1702.655 784.7 1703.175 ;
    END
  END sb_clint_mtime_put[42]
  PIN sb_clint_mtime_put[43]
    DIRECTION INPUT ;
    USE SIGNAL ;
    PORT
      LAYER Metal4 ;
        RECT  729.54 1702.655 729.82 1703.175 ;
    END
  END sb_clint_mtime_put[43]
  PIN sb_clint_mtime_put[44]
    DIRECTION INPUT ;
    USE SIGNAL ;
    PORT
      LAYER Metal4 ;
        RECT  720.58 1702.655 720.86 1703.175 ;
    END
  END sb_clint_mtime_put[44]
  PIN sb_clint_mtime_put[45]
    DIRECTION INPUT ;
    USE SIGNAL ;
    PORT
      LAYER Metal4 ;
        RECT  699.3 1702.655 699.58 1703.175 ;
    END
  END sb_clint_mtime_put[45]
  PIN sb_clint_mtime_put[46]
    DIRECTION INPUT ;
    USE SIGNAL ;
    PORT
      LAYER Metal4 ;
        RECT  692.58 1702.655 692.86 1703.175 ;
    END
  END sb_clint_mtime_put[46]
  PIN sb_clint_mtime_put[47]
    DIRECTION INPUT ;
    USE SIGNAL ;
    PORT
      LAYER Metal4 ;
        RECT  672.42 1702.655 672.7 1703.175 ;
    END
  END sb_clint_mtime_put[47]
  PIN sb_clint_mtime_put[48]
    DIRECTION INPUT ;
    USE SIGNAL ;
    PORT
      LAYER Metal3 ;
        RECT  0 1050.98 0.52 1051.26 ;
    END
  END sb_clint_mtime_put[48]
  PIN sb_clint_mtime_put[49]
    DIRECTION INPUT ;
    USE SIGNAL ;
    PORT
      LAYER Metal4 ;
        RECT  657.86 1702.655 658.14 1703.175 ;
    END
  END sb_clint_mtime_put[49]
  PIN sb_clint_mtime_put[4]
    DIRECTION INPUT ;
    USE SIGNAL ;
    PORT
      LAYER Metal4 ;
        RECT  1006.18 1702.655 1006.46 1703.175 ;
    END
  END sb_clint_mtime_put[4]
  PIN sb_clint_mtime_put[50]
    DIRECTION INPUT ;
    USE SIGNAL ;
    PORT
      LAYER Metal3 ;
        RECT  0 1143.94 0.52 1144.22 ;
    END
  END sb_clint_mtime_put[50]
  PIN sb_clint_mtime_put[51]
    DIRECTION INPUT ;
    USE SIGNAL ;
    PORT
      LAYER Metal4 ;
        RECT  518.98 1702.655 519.26 1703.175 ;
    END
  END sb_clint_mtime_put[51]
  PIN sb_clint_mtime_put[52]
    DIRECTION INPUT ;
    USE SIGNAL ;
    PORT
      LAYER Metal4 ;
        RECT  548.1 1702.655 548.38 1703.175 ;
    END
  END sb_clint_mtime_put[52]
  PIN sb_clint_mtime_put[53]
    DIRECTION INPUT ;
    USE SIGNAL ;
    PORT
      LAYER Metal4 ;
        RECT  469.7 1702.655 469.98 1703.175 ;
    END
  END sb_clint_mtime_put[53]
  PIN sb_clint_mtime_put[54]
    DIRECTION INPUT ;
    USE SIGNAL ;
    PORT
      LAYER Metal3 ;
        RECT  0 1024.1 0.52 1024.38 ;
    END
  END sb_clint_mtime_put[54]
  PIN sb_clint_mtime_put[55]
    DIRECTION INPUT ;
    USE SIGNAL ;
    PORT
      LAYER Metal4 ;
        RECT  476.42 1702.655 476.7 1703.175 ;
    END
  END sb_clint_mtime_put[55]
  PIN sb_clint_mtime_put[56]
    DIRECTION INPUT ;
    USE SIGNAL ;
    PORT
      LAYER Metal3 ;
        RECT  0 1043.14 0.52 1043.42 ;
    END
  END sb_clint_mtime_put[56]
  PIN sb_clint_mtime_put[57]
    DIRECTION INPUT ;
    USE SIGNAL ;
    PORT
      LAYER Metal4 ;
        RECT  477.54 1702.655 477.82 1703.175 ;
    END
  END sb_clint_mtime_put[57]
  PIN sb_clint_mtime_put[58]
    DIRECTION INPUT ;
    USE SIGNAL ;
    PORT
      LAYER Metal3 ;
        RECT  0 1034.18 0.52 1034.46 ;
    END
  END sb_clint_mtime_put[58]
  PIN sb_clint_mtime_put[59]
    DIRECTION INPUT ;
    USE SIGNAL ;
    PORT
      LAYER Metal3 ;
        RECT  0 1012.9 0.52 1013.18 ;
    END
  END sb_clint_mtime_put[59]
  PIN sb_clint_mtime_put[5]
    DIRECTION INPUT ;
    USE SIGNAL ;
    PORT
      LAYER Metal4 ;
        RECT  645.54 1702.655 645.82 1703.175 ;
    END
  END sb_clint_mtime_put[5]
  PIN sb_clint_mtime_put[60]
    DIRECTION INPUT ;
    USE SIGNAL ;
    PORT
      LAYER Metal4 ;
        RECT  650.02 1702.655 650.3 1703.175 ;
    END
  END sb_clint_mtime_put[60]
  PIN sb_clint_mtime_put[61]
    DIRECTION INPUT ;
    USE SIGNAL ;
    PORT
      LAYER Metal4 ;
        RECT  648.9 1702.655 649.18 1703.175 ;
    END
  END sb_clint_mtime_put[61]
  PIN sb_clint_mtime_put[62]
    DIRECTION INPUT ;
    USE SIGNAL ;
    PORT
      LAYER Metal4 ;
        RECT  644.42 1702.655 644.7 1703.175 ;
    END
  END sb_clint_mtime_put[62]
  PIN sb_clint_mtime_put[63]
    DIRECTION INPUT ;
    USE SIGNAL ;
    PORT
      LAYER Metal4 ;
        RECT  885.22 1702.655 885.5 1703.175 ;
    END
  END sb_clint_mtime_put[63]
  PIN sb_clint_mtime_put[6]
    DIRECTION INPUT ;
    USE SIGNAL ;
    PORT
      LAYER Metal4 ;
        RECT  544.74 1702.655 545.02 1703.175 ;
    END
  END sb_clint_mtime_put[6]
  PIN sb_clint_mtime_put[7]
    DIRECTION INPUT ;
    USE SIGNAL ;
    PORT
      LAYER Metal4 ;
        RECT  671.3 1702.655 671.58 1703.175 ;
    END
  END sb_clint_mtime_put[7]
  PIN sb_clint_mtime_put[8]
    DIRECTION INPUT ;
    USE SIGNAL ;
    PORT
      LAYER Metal4 ;
        RECT  870.66 1702.655 870.94 1703.175 ;
    END
  END sb_clint_mtime_put[8]
  PIN sb_clint_mtime_put[9]
    DIRECTION INPUT ;
    USE SIGNAL ;
    PORT
      LAYER Metal3 ;
        RECT  0 1210.02 0.52 1210.3 ;
    END
  END sb_clint_mtime_put[9]
  PIN sb_clint_mtip_put
    DIRECTION INPUT ;
    USE SIGNAL ;
    PORT
      LAYER Metal4 ;
        RECT  889.7 1702.655 889.98 1703.175 ;
    END
  END sb_clint_mtip_put
  PIN sb_ext_interrupt_put
    DIRECTION INPUT ;
    USE SIGNAL ;
    PORT
      LAYER Metal4 ;
        RECT  863.94 1702.655 864.22 1703.175 ;
    END
  END sb_ext_interrupt_put
  PIN VDD
    DIRECTION INOUT ;
    USE POWER ;
    PORT
      LAYER Metal5 ;
        RECT  2.24 1615.6 1700.72 1620.08 ;
        RECT  2.24 1526 1700.72 1530.48 ;
        RECT  2.24 1436.4 1700.72 1440.88 ;
        RECT  2.24 1346.8 1700.72 1351.28 ;
        RECT  2.24 1257.2 1700.72 1261.68 ;
        RECT  2.24 1167.6 1700.72 1172.08 ;
        RECT  2.24 1078 1700.72 1082.48 ;
        RECT  2.24 988.4 1700.72 992.88 ;
        RECT  2.24 898.8 1700.72 903.28 ;
        RECT  2.24 809.2 1700.72 813.68 ;
        RECT  2.24 719.6 1700.72 724.08 ;
        RECT  2.24 630 1700.72 634.48 ;
        RECT  2.24 540.4 1700.72 544.88 ;
        RECT  2.24 450.8 1700.72 455.28 ;
        RECT  2.24 361.2 1700.72 365.68 ;
        RECT  2.24 271.6 1700.72 276.08 ;
        RECT  2.24 182 1700.72 186.48 ;
        RECT  2.24 92.4 1700.72 96.88 ;
    END
  END VDD
  PIN VSS
    DIRECTION INOUT ;
    USE GROUND ;
    PORT
      LAYER Metal5 ;
        RECT  2.24 1660.4 1700.72 1664.88 ;
        RECT  2.24 1570.8 1700.72 1575.28 ;
        RECT  2.24 1481.2 1700.72 1485.68 ;
        RECT  2.24 1391.6 1700.72 1396.08 ;
        RECT  2.24 1302 1700.72 1306.48 ;
        RECT  2.24 1212.4 1700.72 1216.88 ;
        RECT  2.24 1122.8 1700.72 1127.28 ;
        RECT  2.24 1033.2 1700.72 1037.68 ;
        RECT  2.24 943.6 1700.72 948.08 ;
        RECT  2.24 854 1700.72 858.48 ;
        RECT  2.24 764.4 1700.72 768.88 ;
        RECT  2.24 674.8 1700.72 679.28 ;
        RECT  2.24 585.2 1700.72 589.68 ;
        RECT  2.24 495.6 1700.72 500.08 ;
        RECT  2.24 406 1700.72 410.48 ;
        RECT  2.24 316.4 1700.72 320.88 ;
        RECT  2.24 226.8 1700.72 231.28 ;
        RECT  2.24 137.2 1700.72 141.68 ;
        RECT  2.24 47.6 1700.72 52.08 ;
    END
  END VSS
  OBS
    LAYER Metal1 ;
     RECT  0 0 1703.175 1703.175 ;
    LAYER Metal2 ;
     RECT  0 0 1703.175 1703.175 ;
    LAYER Metal3 ;
     RECT  0 0 1703.175 1703.175 ;
    LAYER Metal4 ;
     RECT  0 0 1703.175 1703.175 ;
    LAYER Metal5 ;
     RECT  0 0 1703.175 1703.175 ;
  END
END eclass_top
END LIBRARY
